VERSION 5.7 ;
BUSBITCHARS "[]" ;
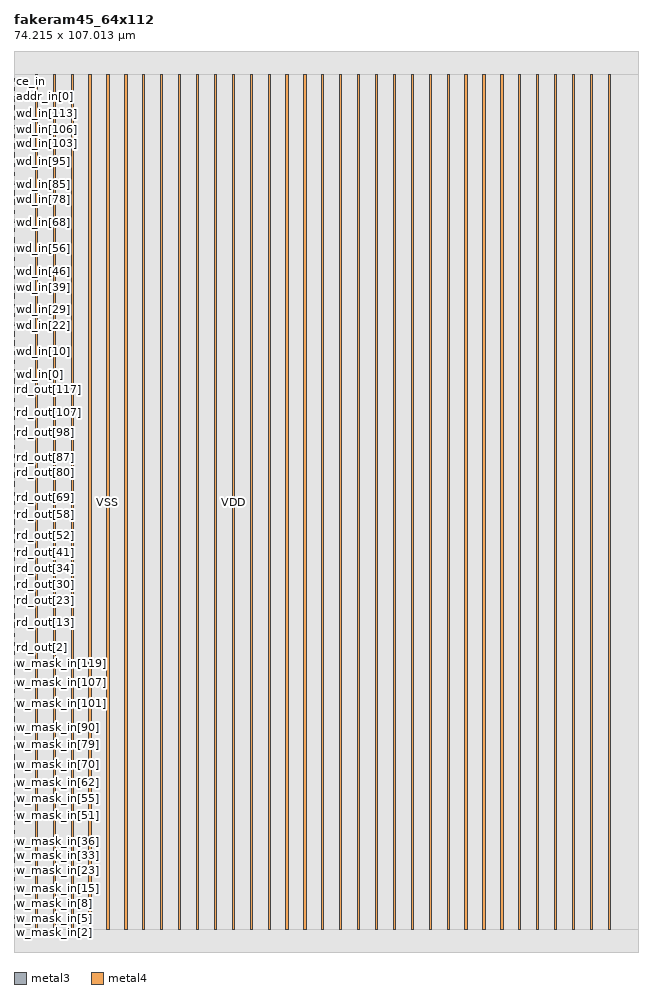
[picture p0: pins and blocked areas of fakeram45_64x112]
MACRO fakeram45_64x112
  FOREIGN fakeram45_64x112 0 0 ;
  SYMMETRY X Y R90 ;
  SIZE 74.215 BY 107.013 ;
  CLASS BLOCK ;
  PIN w_mask_in[0]
    DIRECTION INPUT ;
    USE SIGNAL ;
    SHAPE ABUTMENT ;
    PORT
      LAYER metal3 ;
      RECT 0.000 2.661 0.067 2.728 ;
    END
  END w_mask_in[0]
  PIN w_mask_in[1]
    DIRECTION INPUT ;
    USE SIGNAL ;
    SHAPE ABUTMENT ;
    PORT
      LAYER metal3 ;
      RECT 0.000 2.927 0.067 2.994 ;
    END
  END w_mask_in[1]
  PIN w_mask_in[2]
    DIRECTION INPUT ;
    USE SIGNAL ;
    SHAPE ABUTMENT ;
    PORT
      LAYER metal3 ;
      RECT 0.000 3.193 0.067 3.260 ;
    END
  END w_mask_in[2]
  PIN w_mask_in[3]
    DIRECTION INPUT ;
    USE SIGNAL ;
    SHAPE ABUTMENT ;
    PORT
      LAYER metal3 ;
      RECT 0.000 3.459 0.067 3.526 ;
    END
  END w_mask_in[3]
  PIN w_mask_in[4]
    DIRECTION INPUT ;
    USE SIGNAL ;
    SHAPE ABUTMENT ;
    PORT
      LAYER metal3 ;
      RECT 0.000 3.725 0.067 3.792 ;
    END
  END w_mask_in[4]
  PIN w_mask_in[5]
    DIRECTION INPUT ;
    USE SIGNAL ;
    SHAPE ABUTMENT ;
    PORT
      LAYER metal3 ;
      RECT 0.000 3.992 0.067 4.058 ;
    END
  END w_mask_in[5]
  PIN w_mask_in[6]
    DIRECTION INPUT ;
    USE SIGNAL ;
    SHAPE ABUTMENT ;
    PORT
      LAYER metal3 ;
      RECT 0.000 4.258 0.067 4.324 ;
    END
  END w_mask_in[6]
  PIN w_mask_in[7]
    DIRECTION INPUT ;
    USE SIGNAL ;
    SHAPE ABUTMENT ;
    PORT
      LAYER metal3 ;
      RECT 0.000 4.524 0.067 4.590 ;
    END
  END w_mask_in[7]
  PIN w_mask_in[8]
    DIRECTION INPUT ;
    USE SIGNAL ;
    SHAPE ABUTMENT ;
    PORT
      LAYER metal3 ;
      RECT 0.000 4.790 0.067 4.856 ;
    END
  END w_mask_in[8]
  PIN w_mask_in[9]
    DIRECTION INPUT ;
    USE SIGNAL ;
    SHAPE ABUTMENT ;
    PORT
      LAYER metal3 ;
      RECT 0.000 5.056 0.067 5.123 ;
    END
  END w_mask_in[9]
  PIN w_mask_in[10]
    DIRECTION INPUT ;
    USE SIGNAL ;
    SHAPE ABUTMENT ;
    PORT
      LAYER metal3 ;
      RECT 0.000 5.322 0.067 5.389 ;
    END
  END w_mask_in[10]
  PIN w_mask_in[11]
    DIRECTION INPUT ;
    USE SIGNAL ;
    SHAPE ABUTMENT ;
    PORT
      LAYER metal3 ;
      RECT 0.000 5.588 0.067 5.655 ;
    END
  END w_mask_in[11]
  PIN w_mask_in[12]
    DIRECTION INPUT ;
    USE SIGNAL ;
    SHAPE ABUTMENT ;
    PORT
      LAYER metal3 ;
      RECT 0.000 5.854 0.067 5.921 ;
    END
  END w_mask_in[12]
  PIN w_mask_in[13]
    DIRECTION INPUT ;
    USE SIGNAL ;
    SHAPE ABUTMENT ;
    PORT
      LAYER metal3 ;
      RECT 0.000 6.120 0.067 6.187 ;
    END
  END w_mask_in[13]
  PIN w_mask_in[14]
    DIRECTION INPUT ;
    USE SIGNAL ;
    SHAPE ABUTMENT ;
    PORT
      LAYER metal3 ;
      RECT 0.000 6.387 0.067 6.453 ;
    END
  END w_mask_in[14]
  PIN w_mask_in[15]
    DIRECTION INPUT ;
    USE SIGNAL ;
    SHAPE ABUTMENT ;
    PORT
      LAYER metal3 ;
      RECT 0.000 6.653 0.067 6.719 ;
    END
  END w_mask_in[15]
  PIN w_mask_in[16]
    DIRECTION INPUT ;
    USE SIGNAL ;
    SHAPE ABUTMENT ;
    PORT
      LAYER metal3 ;
      RECT 0.000 6.919 0.067 6.985 ;
    END
  END w_mask_in[16]
  PIN w_mask_in[17]
    DIRECTION INPUT ;
    USE SIGNAL ;
    SHAPE ABUTMENT ;
    PORT
      LAYER metal3 ;
      RECT 0.000 7.185 0.067 7.251 ;
    END
  END w_mask_in[17]
  PIN w_mask_in[18]
    DIRECTION INPUT ;
    USE SIGNAL ;
    SHAPE ABUTMENT ;
    PORT
      LAYER metal3 ;
      RECT 0.000 7.451 0.067 7.518 ;
    END
  END w_mask_in[18]
  PIN w_mask_in[19]
    DIRECTION INPUT ;
    USE SIGNAL ;
    SHAPE ABUTMENT ;
    PORT
      LAYER metal3 ;
      RECT 0.000 7.717 0.067 7.784 ;
    END
  END w_mask_in[19]
  PIN w_mask_in[20]
    DIRECTION INPUT ;
    USE SIGNAL ;
    SHAPE ABUTMENT ;
    PORT
      LAYER metal3 ;
      RECT 0.000 7.983 0.067 8.050 ;
    END
  END w_mask_in[20]
  PIN w_mask_in[21]
    DIRECTION INPUT ;
    USE SIGNAL ;
    SHAPE ABUTMENT ;
    PORT
      LAYER metal3 ;
      RECT 0.000 8.249 0.067 8.316 ;
    END
  END w_mask_in[21]
  PIN w_mask_in[22]
    DIRECTION INPUT ;
    USE SIGNAL ;
    SHAPE ABUTMENT ;
    PORT
      LAYER metal3 ;
      RECT 0.000 8.515 0.067 8.582 ;
    END
  END w_mask_in[22]
  PIN w_mask_in[23]
    DIRECTION INPUT ;
    USE SIGNAL ;
    SHAPE ABUTMENT ;
    PORT
      LAYER metal3 ;
      RECT 0.000 8.782 0.067 8.848 ;
    END
  END w_mask_in[23]
  PIN w_mask_in[24]
    DIRECTION INPUT ;
    USE SIGNAL ;
    SHAPE ABUTMENT ;
    PORT
      LAYER metal3 ;
      RECT 0.000 9.048 0.067 9.114 ;
    END
  END w_mask_in[24]
  PIN w_mask_in[25]
    DIRECTION INPUT ;
    USE SIGNAL ;
    SHAPE ABUTMENT ;
    PORT
      LAYER metal3 ;
      RECT 0.000 9.314 0.067 9.380 ;
    END
  END w_mask_in[25]
  PIN w_mask_in[26]
    DIRECTION INPUT ;
    USE SIGNAL ;
    SHAPE ABUTMENT ;
    PORT
      LAYER metal3 ;
      RECT 0.000 9.580 0.067 9.646 ;
    END
  END w_mask_in[26]
  PIN w_mask_in[27]
    DIRECTION INPUT ;
    USE SIGNAL ;
    SHAPE ABUTMENT ;
    PORT
      LAYER metal3 ;
      RECT 0.000 9.846 0.067 9.912 ;
    END
  END w_mask_in[27]
  PIN w_mask_in[28]
    DIRECTION INPUT ;
    USE SIGNAL ;
    SHAPE ABUTMENT ;
    PORT
      LAYER metal3 ;
      RECT 0.000 10.112 0.067 10.179 ;
    END
  END w_mask_in[28]
  PIN w_mask_in[29]
    DIRECTION INPUT ;
    USE SIGNAL ;
    SHAPE ABUTMENT ;
    PORT
      LAYER metal3 ;
      RECT 0.000 10.378 0.067 10.445 ;
    END
  END w_mask_in[29]
  PIN w_mask_in[30]
    DIRECTION INPUT ;
    USE SIGNAL ;
    SHAPE ABUTMENT ;
    PORT
      LAYER metal3 ;
      RECT 0.000 10.644 0.067 10.711 ;
    END
  END w_mask_in[30]
  PIN w_mask_in[31]
    DIRECTION INPUT ;
    USE SIGNAL ;
    SHAPE ABUTMENT ;
    PORT
      LAYER metal3 ;
      RECT 0.000 10.910 0.067 10.977 ;
    END
  END w_mask_in[31]
  PIN w_mask_in[32]
    DIRECTION INPUT ;
    USE SIGNAL ;
    SHAPE ABUTMENT ;
    PORT
      LAYER metal3 ;
      RECT 0.000 11.176 0.067 11.243 ;
    END
  END w_mask_in[32]
  PIN w_mask_in[33]
    DIRECTION INPUT ;
    USE SIGNAL ;
    SHAPE ABUTMENT ;
    PORT
      LAYER metal3 ;
      RECT 0.000 11.443 0.067 11.509 ;
    END
  END w_mask_in[33]
  PIN w_mask_in[34]
    DIRECTION INPUT ;
    USE SIGNAL ;
    SHAPE ABUTMENT ;
    PORT
      LAYER metal3 ;
      RECT 0.000 11.709 0.067 11.775 ;
    END
  END w_mask_in[34]
  PIN w_mask_in[35]
    DIRECTION INPUT ;
    USE SIGNAL ;
    SHAPE ABUTMENT ;
    PORT
      LAYER metal3 ;
      RECT 0.000 11.975 0.067 12.041 ;
    END
  END w_mask_in[35]
  PIN w_mask_in[36]
    DIRECTION INPUT ;
    USE SIGNAL ;
    SHAPE ABUTMENT ;
    PORT
      LAYER metal3 ;
      RECT 0.000 12.241 0.067 12.307 ;
    END
  END w_mask_in[36]
  PIN w_mask_in[37]
    DIRECTION INPUT ;
    USE SIGNAL ;
    SHAPE ABUTMENT ;
    PORT
      LAYER metal3 ;
      RECT 0.000 12.507 0.067 12.574 ;
    END
  END w_mask_in[37]
  PIN w_mask_in[38]
    DIRECTION INPUT ;
    USE SIGNAL ;
    SHAPE ABUTMENT ;
    PORT
      LAYER metal3 ;
      RECT 0.000 12.773 0.067 12.840 ;
    END
  END w_mask_in[38]
  PIN w_mask_in[39]
    DIRECTION INPUT ;
    USE SIGNAL ;
    SHAPE ABUTMENT ;
    PORT
      LAYER metal3 ;
      RECT 0.000 13.039 0.067 13.106 ;
    END
  END w_mask_in[39]
  PIN w_mask_in[40]
    DIRECTION INPUT ;
    USE SIGNAL ;
    SHAPE ABUTMENT ;
    PORT
      LAYER metal3 ;
      RECT 0.000 13.305 0.067 13.372 ;
    END
  END w_mask_in[40]
  PIN w_mask_in[41]
    DIRECTION INPUT ;
    USE SIGNAL ;
    SHAPE ABUTMENT ;
    PORT
      LAYER metal3 ;
      RECT 0.000 13.571 0.067 13.638 ;
    END
  END w_mask_in[41]
  PIN w_mask_in[42]
    DIRECTION INPUT ;
    USE SIGNAL ;
    SHAPE ABUTMENT ;
    PORT
      LAYER metal3 ;
      RECT 0.000 13.838 0.067 13.904 ;
    END
  END w_mask_in[42]
  PIN w_mask_in[43]
    DIRECTION INPUT ;
    USE SIGNAL ;
    SHAPE ABUTMENT ;
    PORT
      LAYER metal3 ;
      RECT 0.000 14.104 0.067 14.170 ;
    END
  END w_mask_in[43]
  PIN w_mask_in[44]
    DIRECTION INPUT ;
    USE SIGNAL ;
    SHAPE ABUTMENT ;
    PORT
      LAYER metal3 ;
      RECT 0.000 14.370 0.067 14.436 ;
    END
  END w_mask_in[44]
  PIN w_mask_in[45]
    DIRECTION INPUT ;
    USE SIGNAL ;
    SHAPE ABUTMENT ;
    PORT
      LAYER metal3 ;
      RECT 0.000 14.636 0.067 14.702 ;
    END
  END w_mask_in[45]
  PIN w_mask_in[46]
    DIRECTION INPUT ;
    USE SIGNAL ;
    SHAPE ABUTMENT ;
    PORT
      LAYER metal3 ;
      RECT 0.000 14.902 0.067 14.969 ;
    END
  END w_mask_in[46]
  PIN w_mask_in[47]
    DIRECTION INPUT ;
    USE SIGNAL ;
    SHAPE ABUTMENT ;
    PORT
      LAYER metal3 ;
      RECT 0.000 15.168 0.067 15.235 ;
    END
  END w_mask_in[47]
  PIN w_mask_in[48]
    DIRECTION INPUT ;
    USE SIGNAL ;
    SHAPE ABUTMENT ;
    PORT
      LAYER metal3 ;
      RECT 0.000 15.434 0.067 15.501 ;
    END
  END w_mask_in[48]
  PIN w_mask_in[49]
    DIRECTION INPUT ;
    USE SIGNAL ;
    SHAPE ABUTMENT ;
    PORT
      LAYER metal3 ;
      RECT 0.000 15.700 0.067 15.767 ;
    END
  END w_mask_in[49]
  PIN w_mask_in[50]
    DIRECTION INPUT ;
    USE SIGNAL ;
    SHAPE ABUTMENT ;
    PORT
      LAYER metal3 ;
      RECT 0.000 15.966 0.067 16.033 ;
    END
  END w_mask_in[50]
  PIN w_mask_in[51]
    DIRECTION INPUT ;
    USE SIGNAL ;
    SHAPE ABUTMENT ;
    PORT
      LAYER metal3 ;
      RECT 0.000 16.233 0.067 16.299 ;
    END
  END w_mask_in[51]
  PIN w_mask_in[52]
    DIRECTION INPUT ;
    USE SIGNAL ;
    SHAPE ABUTMENT ;
    PORT
      LAYER metal3 ;
      RECT 0.000 16.499 0.067 16.565 ;
    END
  END w_mask_in[52]
  PIN w_mask_in[53]
    DIRECTION INPUT ;
    USE SIGNAL ;
    SHAPE ABUTMENT ;
    PORT
      LAYER metal3 ;
      RECT 0.000 16.765 0.067 16.831 ;
    END
  END w_mask_in[53]
  PIN w_mask_in[54]
    DIRECTION INPUT ;
    USE SIGNAL ;
    SHAPE ABUTMENT ;
    PORT
      LAYER metal3 ;
      RECT 0.000 17.031 0.067 17.097 ;
    END
  END w_mask_in[54]
  PIN w_mask_in[55]
    DIRECTION INPUT ;
    USE SIGNAL ;
    SHAPE ABUTMENT ;
    PORT
      LAYER metal3 ;
      RECT 0.000 17.297 0.067 17.363 ;
    END
  END w_mask_in[55]
  PIN w_mask_in[56]
    DIRECTION INPUT ;
    USE SIGNAL ;
    SHAPE ABUTMENT ;
    PORT
      LAYER metal3 ;
      RECT 0.000 17.563 0.067 17.630 ;
    END
  END w_mask_in[56]
  PIN w_mask_in[57]
    DIRECTION INPUT ;
    USE SIGNAL ;
    SHAPE ABUTMENT ;
    PORT
      LAYER metal3 ;
      RECT 0.000 17.829 0.067 17.896 ;
    END
  END w_mask_in[57]
  PIN w_mask_in[58]
    DIRECTION INPUT ;
    USE SIGNAL ;
    SHAPE ABUTMENT ;
    PORT
      LAYER metal3 ;
      RECT 0.000 18.095 0.067 18.162 ;
    END
  END w_mask_in[58]
  PIN w_mask_in[59]
    DIRECTION INPUT ;
    USE SIGNAL ;
    SHAPE ABUTMENT ;
    PORT
      LAYER metal3 ;
      RECT 0.000 18.361 0.067 18.428 ;
    END
  END w_mask_in[59]
  PIN w_mask_in[60]
    DIRECTION INPUT ;
    USE SIGNAL ;
    SHAPE ABUTMENT ;
    PORT
      LAYER metal3 ;
      RECT 0.000 18.627 0.067 18.694 ;
    END
  END w_mask_in[60]
  PIN w_mask_in[61]
    DIRECTION INPUT ;
    USE SIGNAL ;
    SHAPE ABUTMENT ;
    PORT
      LAYER metal3 ;
      RECT 0.000 18.894 0.067 18.960 ;
    END
  END w_mask_in[61]
  PIN w_mask_in[62]
    DIRECTION INPUT ;
    USE SIGNAL ;
    SHAPE ABUTMENT ;
    PORT
      LAYER metal3 ;
      RECT 0.000 19.160 0.067 19.226 ;
    END
  END w_mask_in[62]
  PIN w_mask_in[63]
    DIRECTION INPUT ;
    USE SIGNAL ;
    SHAPE ABUTMENT ;
    PORT
      LAYER metal3 ;
      RECT 0.000 19.426 0.067 19.492 ;
    END
  END w_mask_in[63]
  PIN w_mask_in[64]
    DIRECTION INPUT ;
    USE SIGNAL ;
    SHAPE ABUTMENT ;
    PORT
      LAYER metal3 ;
      RECT 0.000 19.692 0.067 19.758 ;
    END
  END w_mask_in[64]
  PIN w_mask_in[65]
    DIRECTION INPUT ;
    USE SIGNAL ;
    SHAPE ABUTMENT ;
    PORT
      LAYER metal3 ;
      RECT 0.000 19.958 0.067 20.025 ;
    END
  END w_mask_in[65]
  PIN w_mask_in[66]
    DIRECTION INPUT ;
    USE SIGNAL ;
    SHAPE ABUTMENT ;
    PORT
      LAYER metal3 ;
      RECT 0.000 20.224 0.067 20.291 ;
    END
  END w_mask_in[66]
  PIN w_mask_in[67]
    DIRECTION INPUT ;
    USE SIGNAL ;
    SHAPE ABUTMENT ;
    PORT
      LAYER metal3 ;
      RECT 0.000 20.490 0.067 20.557 ;
    END
  END w_mask_in[67]
  PIN w_mask_in[68]
    DIRECTION INPUT ;
    USE SIGNAL ;
    SHAPE ABUTMENT ;
    PORT
      LAYER metal3 ;
      RECT 0.000 20.756 0.067 20.823 ;
    END
  END w_mask_in[68]
  PIN w_mask_in[69]
    DIRECTION INPUT ;
    USE SIGNAL ;
    SHAPE ABUTMENT ;
    PORT
      LAYER metal3 ;
      RECT 0.000 21.022 0.067 21.089 ;
    END
  END w_mask_in[69]
  PIN w_mask_in[70]
    DIRECTION INPUT ;
    USE SIGNAL ;
    SHAPE ABUTMENT ;
    PORT
      LAYER metal3 ;
      RECT 0.000 21.289 0.067 21.355 ;
    END
  END w_mask_in[70]
  PIN w_mask_in[71]
    DIRECTION INPUT ;
    USE SIGNAL ;
    SHAPE ABUTMENT ;
    PORT
      LAYER metal3 ;
      RECT 0.000 21.555 0.067 21.621 ;
    END
  END w_mask_in[71]
  PIN w_mask_in[72]
    DIRECTION INPUT ;
    USE SIGNAL ;
    SHAPE ABUTMENT ;
    PORT
      LAYER metal3 ;
      RECT 0.000 21.821 0.067 21.887 ;
    END
  END w_mask_in[72]
  PIN w_mask_in[73]
    DIRECTION INPUT ;
    USE SIGNAL ;
    SHAPE ABUTMENT ;
    PORT
      LAYER metal3 ;
      RECT 0.000 22.087 0.067 22.153 ;
    END
  END w_mask_in[73]
  PIN w_mask_in[74]
    DIRECTION INPUT ;
    USE SIGNAL ;
    SHAPE ABUTMENT ;
    PORT
      LAYER metal3 ;
      RECT 0.000 22.353 0.067 22.420 ;
    END
  END w_mask_in[74]
  PIN w_mask_in[75]
    DIRECTION INPUT ;
    USE SIGNAL ;
    SHAPE ABUTMENT ;
    PORT
      LAYER metal3 ;
      RECT 0.000 22.619 0.067 22.686 ;
    END
  END w_mask_in[75]
  PIN w_mask_in[76]
    DIRECTION INPUT ;
    USE SIGNAL ;
    SHAPE ABUTMENT ;
    PORT
      LAYER metal3 ;
      RECT 0.000 22.885 0.067 22.952 ;
    END
  END w_mask_in[76]
  PIN w_mask_in[77]
    DIRECTION INPUT ;
    USE SIGNAL ;
    SHAPE ABUTMENT ;
    PORT
      LAYER metal3 ;
      RECT 0.000 23.151 0.067 23.218 ;
    END
  END w_mask_in[77]
  PIN w_mask_in[78]
    DIRECTION INPUT ;
    USE SIGNAL ;
    SHAPE ABUTMENT ;
    PORT
      LAYER metal3 ;
      RECT 0.000 23.417 0.067 23.484 ;
    END
  END w_mask_in[78]
  PIN w_mask_in[79]
    DIRECTION INPUT ;
    USE SIGNAL ;
    SHAPE ABUTMENT ;
    PORT
      LAYER metal3 ;
      RECT 0.000 23.684 0.067 23.750 ;
    END
  END w_mask_in[79]
  PIN w_mask_in[80]
    DIRECTION INPUT ;
    USE SIGNAL ;
    SHAPE ABUTMENT ;
    PORT
      LAYER metal3 ;
      RECT 0.000 23.950 0.067 24.016 ;
    END
  END w_mask_in[80]
  PIN w_mask_in[81]
    DIRECTION INPUT ;
    USE SIGNAL ;
    SHAPE ABUTMENT ;
    PORT
      LAYER metal3 ;
      RECT 0.000 24.216 0.067 24.282 ;
    END
  END w_mask_in[81]
  PIN w_mask_in[82]
    DIRECTION INPUT ;
    USE SIGNAL ;
    SHAPE ABUTMENT ;
    PORT
      LAYER metal3 ;
      RECT 0.000 24.482 0.067 24.548 ;
    END
  END w_mask_in[82]
  PIN w_mask_in[83]
    DIRECTION INPUT ;
    USE SIGNAL ;
    SHAPE ABUTMENT ;
    PORT
      LAYER metal3 ;
      RECT 0.000 24.748 0.067 24.814 ;
    END
  END w_mask_in[83]
  PIN w_mask_in[84]
    DIRECTION INPUT ;
    USE SIGNAL ;
    SHAPE ABUTMENT ;
    PORT
      LAYER metal3 ;
      RECT 0.000 25.014 0.067 25.081 ;
    END
  END w_mask_in[84]
  PIN w_mask_in[85]
    DIRECTION INPUT ;
    USE SIGNAL ;
    SHAPE ABUTMENT ;
    PORT
      LAYER metal3 ;
      RECT 0.000 25.280 0.067 25.347 ;
    END
  END w_mask_in[85]
  PIN w_mask_in[86]
    DIRECTION INPUT ;
    USE SIGNAL ;
    SHAPE ABUTMENT ;
    PORT
      LAYER metal3 ;
      RECT 0.000 25.546 0.067 25.613 ;
    END
  END w_mask_in[86]
  PIN w_mask_in[87]
    DIRECTION INPUT ;
    USE SIGNAL ;
    SHAPE ABUTMENT ;
    PORT
      LAYER metal3 ;
      RECT 0.000 25.812 0.067 25.879 ;
    END
  END w_mask_in[87]
  PIN w_mask_in[88]
    DIRECTION INPUT ;
    USE SIGNAL ;
    SHAPE ABUTMENT ;
    PORT
      LAYER metal3 ;
      RECT 0.000 26.078 0.067 26.145 ;
    END
  END w_mask_in[88]
  PIN w_mask_in[89]
    DIRECTION INPUT ;
    USE SIGNAL ;
    SHAPE ABUTMENT ;
    PORT
      LAYER metal3 ;
      RECT 0.000 26.345 0.067 26.411 ;
    END
  END w_mask_in[89]
  PIN w_mask_in[90]
    DIRECTION INPUT ;
    USE SIGNAL ;
    SHAPE ABUTMENT ;
    PORT
      LAYER metal3 ;
      RECT 0.000 26.611 0.067 26.677 ;
    END
  END w_mask_in[90]
  PIN w_mask_in[91]
    DIRECTION INPUT ;
    USE SIGNAL ;
    SHAPE ABUTMENT ;
    PORT
      LAYER metal3 ;
      RECT 0.000 26.877 0.067 26.943 ;
    END
  END w_mask_in[91]
  PIN w_mask_in[92]
    DIRECTION INPUT ;
    USE SIGNAL ;
    SHAPE ABUTMENT ;
    PORT
      LAYER metal3 ;
      RECT 0.000 27.143 0.067 27.209 ;
    END
  END w_mask_in[92]
  PIN w_mask_in[93]
    DIRECTION INPUT ;
    USE SIGNAL ;
    SHAPE ABUTMENT ;
    PORT
      LAYER metal3 ;
      RECT 0.000 27.409 0.067 27.476 ;
    END
  END w_mask_in[93]
  PIN w_mask_in[94]
    DIRECTION INPUT ;
    USE SIGNAL ;
    SHAPE ABUTMENT ;
    PORT
      LAYER metal3 ;
      RECT 0.000 27.675 0.067 27.742 ;
    END
  END w_mask_in[94]
  PIN w_mask_in[95]
    DIRECTION INPUT ;
    USE SIGNAL ;
    SHAPE ABUTMENT ;
    PORT
      LAYER metal3 ;
      RECT 0.000 27.941 0.067 28.008 ;
    END
  END w_mask_in[95]
  PIN w_mask_in[96]
    DIRECTION INPUT ;
    USE SIGNAL ;
    SHAPE ABUTMENT ;
    PORT
      LAYER metal3 ;
      RECT 0.000 28.207 0.067 28.274 ;
    END
  END w_mask_in[96]
  PIN w_mask_in[97]
    DIRECTION INPUT ;
    USE SIGNAL ;
    SHAPE ABUTMENT ;
    PORT
      LAYER metal3 ;
      RECT 0.000 28.473 0.067 28.540 ;
    END
  END w_mask_in[97]
  PIN w_mask_in[98]
    DIRECTION INPUT ;
    USE SIGNAL ;
    SHAPE ABUTMENT ;
    PORT
      LAYER metal3 ;
      RECT 0.000 28.740 0.067 28.806 ;
    END
  END w_mask_in[98]
  PIN w_mask_in[99]
    DIRECTION INPUT ;
    USE SIGNAL ;
    SHAPE ABUTMENT ;
    PORT
      LAYER metal3 ;
      RECT 0.000 29.006 0.067 29.072 ;
    END
  END w_mask_in[99]
  PIN w_mask_in[100]
    DIRECTION INPUT ;
    USE SIGNAL ;
    SHAPE ABUTMENT ;
    PORT
      LAYER metal3 ;
      RECT 0.000 29.272 0.067 29.338 ;
    END
  END w_mask_in[100]
  PIN w_mask_in[101]
    DIRECTION INPUT ;
    USE SIGNAL ;
    SHAPE ABUTMENT ;
    PORT
      LAYER metal3 ;
      RECT 0.000 29.538 0.067 29.604 ;
    END
  END w_mask_in[101]
  PIN w_mask_in[102]
    DIRECTION INPUT ;
    USE SIGNAL ;
    SHAPE ABUTMENT ;
    PORT
      LAYER metal3 ;
      RECT 0.000 29.804 0.067 29.871 ;
    END
  END w_mask_in[102]
  PIN w_mask_in[103]
    DIRECTION INPUT ;
    USE SIGNAL ;
    SHAPE ABUTMENT ;
    PORT
      LAYER metal3 ;
      RECT 0.000 30.070 0.067 30.137 ;
    END
  END w_mask_in[103]
  PIN w_mask_in[104]
    DIRECTION INPUT ;
    USE SIGNAL ;
    SHAPE ABUTMENT ;
    PORT
      LAYER metal3 ;
      RECT 0.000 30.336 0.067 30.403 ;
    END
  END w_mask_in[104]
  PIN w_mask_in[105]
    DIRECTION INPUT ;
    USE SIGNAL ;
    SHAPE ABUTMENT ;
    PORT
      LAYER metal3 ;
      RECT 0.000 30.602 0.067 30.669 ;
    END
  END w_mask_in[105]
  PIN w_mask_in[106]
    DIRECTION INPUT ;
    USE SIGNAL ;
    SHAPE ABUTMENT ;
    PORT
      LAYER metal3 ;
      RECT 0.000 30.868 0.067 30.935 ;
    END
  END w_mask_in[106]
  PIN w_mask_in[107]
    DIRECTION INPUT ;
    USE SIGNAL ;
    SHAPE ABUTMENT ;
    PORT
      LAYER metal3 ;
      RECT 0.000 31.135 0.067 31.201 ;
    END
  END w_mask_in[107]
  PIN w_mask_in[108]
    DIRECTION INPUT ;
    USE SIGNAL ;
    SHAPE ABUTMENT ;
    PORT
      LAYER metal3 ;
      RECT 0.000 31.401 0.067 31.467 ;
    END
  END w_mask_in[108]
  PIN w_mask_in[109]
    DIRECTION INPUT ;
    USE SIGNAL ;
    SHAPE ABUTMENT ;
    PORT
      LAYER metal3 ;
      RECT 0.000 31.667 0.067 31.733 ;
    END
  END w_mask_in[109]
  PIN w_mask_in[110]
    DIRECTION INPUT ;
    USE SIGNAL ;
    SHAPE ABUTMENT ;
    PORT
      LAYER metal3 ;
      RECT 0.000 31.933 0.067 31.999 ;
    END
  END w_mask_in[110]
  PIN w_mask_in[111]
    DIRECTION INPUT ;
    USE SIGNAL ;
    SHAPE ABUTMENT ;
    PORT
      LAYER metal3 ;
      RECT 0.000 32.199 0.067 32.265 ;
    END
  END w_mask_in[111]
  PIN w_mask_in[112]
    DIRECTION INPUT ;
    USE SIGNAL ;
    SHAPE ABUTMENT ;
    PORT
      LAYER metal3 ;
      RECT 0.000 32.465 0.067 32.532 ;
    END
  END w_mask_in[112]
  PIN w_mask_in[113]
    DIRECTION INPUT ;
    USE SIGNAL ;
    SHAPE ABUTMENT ;
    PORT
      LAYER metal3 ;
      RECT 0.000 32.731 0.067 32.798 ;
    END
  END w_mask_in[113]
  PIN w_mask_in[114]
    DIRECTION INPUT ;
    USE SIGNAL ;
    SHAPE ABUTMENT ;
    PORT
      LAYER metal3 ;
      RECT 0.000 32.997 0.067 33.064 ;
    END
  END w_mask_in[114]
  PIN w_mask_in[115]
    DIRECTION INPUT ;
    USE SIGNAL ;
    SHAPE ABUTMENT ;
    PORT
      LAYER metal3 ;
      RECT 0.000 33.263 0.067 33.330 ;
    END
  END w_mask_in[115]
  PIN w_mask_in[116]
    DIRECTION INPUT ;
    USE SIGNAL ;
    SHAPE ABUTMENT ;
    PORT
      LAYER metal3 ;
      RECT 0.000 33.529 0.067 33.596 ;
    END
  END w_mask_in[116]
  PIN w_mask_in[117]
    DIRECTION INPUT ;
    USE SIGNAL ;
    SHAPE ABUTMENT ;
    PORT
      LAYER metal3 ;
      RECT 0.000 33.796 0.067 33.862 ;
    END
  END w_mask_in[117]
  PIN w_mask_in[118]
    DIRECTION INPUT ;
    USE SIGNAL ;
    SHAPE ABUTMENT ;
    PORT
      LAYER metal3 ;
      RECT 0.000 34.062 0.067 34.128 ;
    END
  END w_mask_in[118]
  PIN w_mask_in[119]
    DIRECTION INPUT ;
    USE SIGNAL ;
    SHAPE ABUTMENT ;
    PORT
      LAYER metal3 ;
      RECT 0.000 34.328 0.067 34.394 ;
    END
  END w_mask_in[119]
  PIN w_mask_in[120]
    DIRECTION INPUT ;
    USE SIGNAL ;
    SHAPE ABUTMENT ;
    PORT
      LAYER metal3 ;
      RECT 0.000 34.594 0.067 34.660 ;
    END
  END w_mask_in[120]
  PIN w_mask_in[121]
    DIRECTION INPUT ;
    USE SIGNAL ;
    SHAPE ABUTMENT ;
    PORT
      LAYER metal3 ;
      RECT 0.000 34.860 0.067 34.927 ;
    END
  END w_mask_in[121]
  PIN w_mask_in[122]
    DIRECTION INPUT ;
    USE SIGNAL ;
    SHAPE ABUTMENT ;
    PORT
      LAYER metal3 ;
      RECT 0.000 35.126 0.067 35.193 ;
    END
  END w_mask_in[122]
  PIN w_mask_in[123]
    DIRECTION INPUT ;
    USE SIGNAL ;
    SHAPE ABUTMENT ;
    PORT
      LAYER metal3 ;
      RECT 0.000 35.392 0.067 35.459 ;
    END
  END w_mask_in[123]
  PIN rd_out[0]
    DIRECTION OUTPUT ;
    USE SIGNAL ;
    SHAPE ABUTMENT ;
    PORT
      LAYER metal3 ;
      RECT 0.000 35.658 0.067 35.725 ;
    END
  END rd_out[0]
  PIN rd_out[1]
    DIRECTION OUTPUT ;
    USE SIGNAL ;
    SHAPE ABUTMENT ;
    PORT
      LAYER metal3 ;
      RECT 0.000 35.924 0.067 35.991 ;
    END
  END rd_out[1]
  PIN rd_out[2]
    DIRECTION OUTPUT ;
    USE SIGNAL ;
    SHAPE ABUTMENT ;
    PORT
      LAYER metal3 ;
      RECT 0.000 36.191 0.067 36.257 ;
    END
  END rd_out[2]
  PIN rd_out[3]
    DIRECTION OUTPUT ;
    USE SIGNAL ;
    SHAPE ABUTMENT ;
    PORT
      LAYER metal3 ;
      RECT 0.000 36.457 0.067 36.523 ;
    END
  END rd_out[3]
  PIN rd_out[4]
    DIRECTION OUTPUT ;
    USE SIGNAL ;
    SHAPE ABUTMENT ;
    PORT
      LAYER metal3 ;
      RECT 0.000 36.723 0.067 36.789 ;
    END
  END rd_out[4]
  PIN rd_out[5]
    DIRECTION OUTPUT ;
    USE SIGNAL ;
    SHAPE ABUTMENT ;
    PORT
      LAYER metal3 ;
      RECT 0.000 36.989 0.067 37.055 ;
    END
  END rd_out[5]
  PIN rd_out[6]
    DIRECTION OUTPUT ;
    USE SIGNAL ;
    SHAPE ABUTMENT ;
    PORT
      LAYER metal3 ;
      RECT 0.000 37.255 0.067 37.321 ;
    END
  END rd_out[6]
  PIN rd_out[7]
    DIRECTION OUTPUT ;
    USE SIGNAL ;
    SHAPE ABUTMENT ;
    PORT
      LAYER metal3 ;
      RECT 0.000 37.521 0.067 37.588 ;
    END
  END rd_out[7]
  PIN rd_out[8]
    DIRECTION OUTPUT ;
    USE SIGNAL ;
    SHAPE ABUTMENT ;
    PORT
      LAYER metal3 ;
      RECT 0.000 37.787 0.067 37.854 ;
    END
  END rd_out[8]
  PIN rd_out[9]
    DIRECTION OUTPUT ;
    USE SIGNAL ;
    SHAPE ABUTMENT ;
    PORT
      LAYER metal3 ;
      RECT 0.000 38.053 0.067 38.120 ;
    END
  END rd_out[9]
  PIN rd_out[10]
    DIRECTION OUTPUT ;
    USE SIGNAL ;
    SHAPE ABUTMENT ;
    PORT
      LAYER metal3 ;
      RECT 0.000 38.319 0.067 38.386 ;
    END
  END rd_out[10]
  PIN rd_out[11]
    DIRECTION OUTPUT ;
    USE SIGNAL ;
    SHAPE ABUTMENT ;
    PORT
      LAYER metal3 ;
      RECT 0.000 38.586 0.067 38.652 ;
    END
  END rd_out[11]
  PIN rd_out[12]
    DIRECTION OUTPUT ;
    USE SIGNAL ;
    SHAPE ABUTMENT ;
    PORT
      LAYER metal3 ;
      RECT 0.000 38.852 0.067 38.918 ;
    END
  END rd_out[12]
  PIN rd_out[13]
    DIRECTION OUTPUT ;
    USE SIGNAL ;
    SHAPE ABUTMENT ;
    PORT
      LAYER metal3 ;
      RECT 0.000 39.118 0.067 39.184 ;
    END
  END rd_out[13]
  PIN rd_out[14]
    DIRECTION OUTPUT ;
    USE SIGNAL ;
    SHAPE ABUTMENT ;
    PORT
      LAYER metal3 ;
      RECT 0.000 39.384 0.067 39.450 ;
    END
  END rd_out[14]
  PIN rd_out[15]
    DIRECTION OUTPUT ;
    USE SIGNAL ;
    SHAPE ABUTMENT ;
    PORT
      LAYER metal3 ;
      RECT 0.000 39.650 0.067 39.716 ;
    END
  END rd_out[15]
  PIN rd_out[16]
    DIRECTION OUTPUT ;
    USE SIGNAL ;
    SHAPE ABUTMENT ;
    PORT
      LAYER metal3 ;
      RECT 0.000 39.916 0.067 39.983 ;
    END
  END rd_out[16]
  PIN rd_out[17]
    DIRECTION OUTPUT ;
    USE SIGNAL ;
    SHAPE ABUTMENT ;
    PORT
      LAYER metal3 ;
      RECT 0.000 40.182 0.067 40.249 ;
    END
  END rd_out[17]
  PIN rd_out[18]
    DIRECTION OUTPUT ;
    USE SIGNAL ;
    SHAPE ABUTMENT ;
    PORT
      LAYER metal3 ;
      RECT 0.000 40.448 0.067 40.515 ;
    END
  END rd_out[18]
  PIN rd_out[19]
    DIRECTION OUTPUT ;
    USE SIGNAL ;
    SHAPE ABUTMENT ;
    PORT
      LAYER metal3 ;
      RECT 0.000 40.714 0.067 40.781 ;
    END
  END rd_out[19]
  PIN rd_out[20]
    DIRECTION OUTPUT ;
    USE SIGNAL ;
    SHAPE ABUTMENT ;
    PORT
      LAYER metal3 ;
      RECT 0.000 40.980 0.067 41.047 ;
    END
  END rd_out[20]
  PIN rd_out[21]
    DIRECTION OUTPUT ;
    USE SIGNAL ;
    SHAPE ABUTMENT ;
    PORT
      LAYER metal3 ;
      RECT 0.000 41.247 0.067 41.313 ;
    END
  END rd_out[21]
  PIN rd_out[22]
    DIRECTION OUTPUT ;
    USE SIGNAL ;
    SHAPE ABUTMENT ;
    PORT
      LAYER metal3 ;
      RECT 0.000 41.513 0.067 41.579 ;
    END
  END rd_out[22]
  PIN rd_out[23]
    DIRECTION OUTPUT ;
    USE SIGNAL ;
    SHAPE ABUTMENT ;
    PORT
      LAYER metal3 ;
      RECT 0.000 41.779 0.067 41.845 ;
    END
  END rd_out[23]
  PIN rd_out[24]
    DIRECTION OUTPUT ;
    USE SIGNAL ;
    SHAPE ABUTMENT ;
    PORT
      LAYER metal3 ;
      RECT 0.000 42.045 0.067 42.111 ;
    END
  END rd_out[24]
  PIN rd_out[25]
    DIRECTION OUTPUT ;
    USE SIGNAL ;
    SHAPE ABUTMENT ;
    PORT
      LAYER metal3 ;
      RECT 0.000 42.311 0.067 42.378 ;
    END
  END rd_out[25]
  PIN rd_out[26]
    DIRECTION OUTPUT ;
    USE SIGNAL ;
    SHAPE ABUTMENT ;
    PORT
      LAYER metal3 ;
      RECT 0.000 42.577 0.067 42.644 ;
    END
  END rd_out[26]
  PIN rd_out[27]
    DIRECTION OUTPUT ;
    USE SIGNAL ;
    SHAPE ABUTMENT ;
    PORT
      LAYER metal3 ;
      RECT 0.000 42.843 0.067 42.910 ;
    END
  END rd_out[27]
  PIN rd_out[28]
    DIRECTION OUTPUT ;
    USE SIGNAL ;
    SHAPE ABUTMENT ;
    PORT
      LAYER metal3 ;
      RECT 0.000 43.109 0.067 43.176 ;
    END
  END rd_out[28]
  PIN rd_out[29]
    DIRECTION OUTPUT ;
    USE SIGNAL ;
    SHAPE ABUTMENT ;
    PORT
      LAYER metal3 ;
      RECT 0.000 43.375 0.067 43.442 ;
    END
  END rd_out[29]
  PIN rd_out[30]
    DIRECTION OUTPUT ;
    USE SIGNAL ;
    SHAPE ABUTMENT ;
    PORT
      LAYER metal3 ;
      RECT 0.000 43.642 0.067 43.708 ;
    END
  END rd_out[30]
  PIN rd_out[31]
    DIRECTION OUTPUT ;
    USE SIGNAL ;
    SHAPE ABUTMENT ;
    PORT
      LAYER metal3 ;
      RECT 0.000 43.908 0.067 43.974 ;
    END
  END rd_out[31]
  PIN rd_out[32]
    DIRECTION OUTPUT ;
    USE SIGNAL ;
    SHAPE ABUTMENT ;
    PORT
      LAYER metal3 ;
      RECT 0.000 44.174 0.067 44.240 ;
    END
  END rd_out[32]
  PIN rd_out[33]
    DIRECTION OUTPUT ;
    USE SIGNAL ;
    SHAPE ABUTMENT ;
    PORT
      LAYER metal3 ;
      RECT 0.000 44.440 0.067 44.506 ;
    END
  END rd_out[33]
  PIN rd_out[34]
    DIRECTION OUTPUT ;
    USE SIGNAL ;
    SHAPE ABUTMENT ;
    PORT
      LAYER metal3 ;
      RECT 0.000 44.706 0.067 44.772 ;
    END
  END rd_out[34]
  PIN rd_out[35]
    DIRECTION OUTPUT ;
    USE SIGNAL ;
    SHAPE ABUTMENT ;
    PORT
      LAYER metal3 ;
      RECT 0.000 44.972 0.067 45.039 ;
    END
  END rd_out[35]
  PIN rd_out[36]
    DIRECTION OUTPUT ;
    USE SIGNAL ;
    SHAPE ABUTMENT ;
    PORT
      LAYER metal3 ;
      RECT 0.000 45.238 0.067 45.305 ;
    END
  END rd_out[36]
  PIN rd_out[37]
    DIRECTION OUTPUT ;
    USE SIGNAL ;
    SHAPE ABUTMENT ;
    PORT
      LAYER metal3 ;
      RECT 0.000 45.504 0.067 45.571 ;
    END
  END rd_out[37]
  PIN rd_out[38]
    DIRECTION OUTPUT ;
    USE SIGNAL ;
    SHAPE ABUTMENT ;
    PORT
      LAYER metal3 ;
      RECT 0.000 45.770 0.067 45.837 ;
    END
  END rd_out[38]
  PIN rd_out[39]
    DIRECTION OUTPUT ;
    USE SIGNAL ;
    SHAPE ABUTMENT ;
    PORT
      LAYER metal3 ;
      RECT 0.000 46.037 0.067 46.103 ;
    END
  END rd_out[39]
  PIN rd_out[40]
    DIRECTION OUTPUT ;
    USE SIGNAL ;
    SHAPE ABUTMENT ;
    PORT
      LAYER metal3 ;
      RECT 0.000 46.303 0.067 46.369 ;
    END
  END rd_out[40]
  PIN rd_out[41]
    DIRECTION OUTPUT ;
    USE SIGNAL ;
    SHAPE ABUTMENT ;
    PORT
      LAYER metal3 ;
      RECT 0.000 46.569 0.067 46.635 ;
    END
  END rd_out[41]
  PIN rd_out[42]
    DIRECTION OUTPUT ;
    USE SIGNAL ;
    SHAPE ABUTMENT ;
    PORT
      LAYER metal3 ;
      RECT 0.000 46.835 0.067 46.901 ;
    END
  END rd_out[42]
  PIN rd_out[43]
    DIRECTION OUTPUT ;
    USE SIGNAL ;
    SHAPE ABUTMENT ;
    PORT
      LAYER metal3 ;
      RECT 0.000 47.101 0.067 47.167 ;
    END
  END rd_out[43]
  PIN rd_out[44]
    DIRECTION OUTPUT ;
    USE SIGNAL ;
    SHAPE ABUTMENT ;
    PORT
      LAYER metal3 ;
      RECT 0.000 47.367 0.067 47.434 ;
    END
  END rd_out[44]
  PIN rd_out[45]
    DIRECTION OUTPUT ;
    USE SIGNAL ;
    SHAPE ABUTMENT ;
    PORT
      LAYER metal3 ;
      RECT 0.000 47.633 0.067 47.700 ;
    END
  END rd_out[45]
  PIN rd_out[46]
    DIRECTION OUTPUT ;
    USE SIGNAL ;
    SHAPE ABUTMENT ;
    PORT
      LAYER metal3 ;
      RECT 0.000 47.899 0.067 47.966 ;
    END
  END rd_out[46]
  PIN rd_out[47]
    DIRECTION OUTPUT ;
    USE SIGNAL ;
    SHAPE ABUTMENT ;
    PORT
      LAYER metal3 ;
      RECT 0.000 48.165 0.067 48.232 ;
    END
  END rd_out[47]
  PIN rd_out[48]
    DIRECTION OUTPUT ;
    USE SIGNAL ;
    SHAPE ABUTMENT ;
    PORT
      LAYER metal3 ;
      RECT 0.000 48.431 0.067 48.498 ;
    END
  END rd_out[48]
  PIN rd_out[49]
    DIRECTION OUTPUT ;
    USE SIGNAL ;
    SHAPE ABUTMENT ;
    PORT
      LAYER metal3 ;
      RECT 0.000 48.698 0.067 48.764 ;
    END
  END rd_out[49]
  PIN rd_out[50]
    DIRECTION OUTPUT ;
    USE SIGNAL ;
    SHAPE ABUTMENT ;
    PORT
      LAYER metal3 ;
      RECT 0.000 48.964 0.067 49.030 ;
    END
  END rd_out[50]
  PIN rd_out[51]
    DIRECTION OUTPUT ;
    USE SIGNAL ;
    SHAPE ABUTMENT ;
    PORT
      LAYER metal3 ;
      RECT 0.000 49.230 0.067 49.296 ;
    END
  END rd_out[51]
  PIN rd_out[52]
    DIRECTION OUTPUT ;
    USE SIGNAL ;
    SHAPE ABUTMENT ;
    PORT
      LAYER metal3 ;
      RECT 0.000 49.496 0.067 49.562 ;
    END
  END rd_out[52]
  PIN rd_out[53]
    DIRECTION OUTPUT ;
    USE SIGNAL ;
    SHAPE ABUTMENT ;
    PORT
      LAYER metal3 ;
      RECT 0.000 49.762 0.067 49.829 ;
    END
  END rd_out[53]
  PIN rd_out[54]
    DIRECTION OUTPUT ;
    USE SIGNAL ;
    SHAPE ABUTMENT ;
    PORT
      LAYER metal3 ;
      RECT 0.000 50.028 0.067 50.095 ;
    END
  END rd_out[54]
  PIN rd_out[55]
    DIRECTION OUTPUT ;
    USE SIGNAL ;
    SHAPE ABUTMENT ;
    PORT
      LAYER metal3 ;
      RECT 0.000 50.294 0.067 50.361 ;
    END
  END rd_out[55]
  PIN rd_out[56]
    DIRECTION OUTPUT ;
    USE SIGNAL ;
    SHAPE ABUTMENT ;
    PORT
      LAYER metal3 ;
      RECT 0.000 50.560 0.067 50.627 ;
    END
  END rd_out[56]
  PIN rd_out[57]
    DIRECTION OUTPUT ;
    USE SIGNAL ;
    SHAPE ABUTMENT ;
    PORT
      LAYER metal3 ;
      RECT 0.000 50.826 0.067 50.893 ;
    END
  END rd_out[57]
  PIN rd_out[58]
    DIRECTION OUTPUT ;
    USE SIGNAL ;
    SHAPE ABUTMENT ;
    PORT
      LAYER metal3 ;
      RECT 0.000 51.093 0.067 51.159 ;
    END
  END rd_out[58]
  PIN rd_out[59]
    DIRECTION OUTPUT ;
    USE SIGNAL ;
    SHAPE ABUTMENT ;
    PORT
      LAYER metal3 ;
      RECT 0.000 51.359 0.067 51.425 ;
    END
  END rd_out[59]
  PIN rd_out[60]
    DIRECTION OUTPUT ;
    USE SIGNAL ;
    SHAPE ABUTMENT ;
    PORT
      LAYER metal3 ;
      RECT 0.000 51.625 0.067 51.691 ;
    END
  END rd_out[60]
  PIN rd_out[61]
    DIRECTION OUTPUT ;
    USE SIGNAL ;
    SHAPE ABUTMENT ;
    PORT
      LAYER metal3 ;
      RECT 0.000 51.891 0.067 51.957 ;
    END
  END rd_out[61]
  PIN rd_out[62]
    DIRECTION OUTPUT ;
    USE SIGNAL ;
    SHAPE ABUTMENT ;
    PORT
      LAYER metal3 ;
      RECT 0.000 52.157 0.067 52.223 ;
    END
  END rd_out[62]
  PIN rd_out[63]
    DIRECTION OUTPUT ;
    USE SIGNAL ;
    SHAPE ABUTMENT ;
    PORT
      LAYER metal3 ;
      RECT 0.000 52.423 0.067 52.490 ;
    END
  END rd_out[63]
  PIN rd_out[64]
    DIRECTION OUTPUT ;
    USE SIGNAL ;
    SHAPE ABUTMENT ;
    PORT
      LAYER metal3 ;
      RECT 0.000 52.689 0.067 52.756 ;
    END
  END rd_out[64]
  PIN rd_out[65]
    DIRECTION OUTPUT ;
    USE SIGNAL ;
    SHAPE ABUTMENT ;
    PORT
      LAYER metal3 ;
      RECT 0.000 52.955 0.067 53.022 ;
    END
  END rd_out[65]
  PIN rd_out[66]
    DIRECTION OUTPUT ;
    USE SIGNAL ;
    SHAPE ABUTMENT ;
    PORT
      LAYER metal3 ;
      RECT 0.000 53.221 0.067 53.288 ;
    END
  END rd_out[66]
  PIN rd_out[67]
    DIRECTION OUTPUT ;
    USE SIGNAL ;
    SHAPE ABUTMENT ;
    PORT
      LAYER metal3 ;
      RECT 0.000 53.487 0.067 53.554 ;
    END
  END rd_out[67]
  PIN rd_out[68]
    DIRECTION OUTPUT ;
    USE SIGNAL ;
    SHAPE ABUTMENT ;
    PORT
      LAYER metal3 ;
      RECT 0.000 53.754 0.067 53.820 ;
    END
  END rd_out[68]
  PIN rd_out[69]
    DIRECTION OUTPUT ;
    USE SIGNAL ;
    SHAPE ABUTMENT ;
    PORT
      LAYER metal3 ;
      RECT 0.000 54.020 0.067 54.086 ;
    END
  END rd_out[69]
  PIN rd_out[70]
    DIRECTION OUTPUT ;
    USE SIGNAL ;
    SHAPE ABUTMENT ;
    PORT
      LAYER metal3 ;
      RECT 0.000 54.286 0.067 54.352 ;
    END
  END rd_out[70]
  PIN rd_out[71]
    DIRECTION OUTPUT ;
    USE SIGNAL ;
    SHAPE ABUTMENT ;
    PORT
      LAYER metal3 ;
      RECT 0.000 54.552 0.067 54.618 ;
    END
  END rd_out[71]
  PIN rd_out[72]
    DIRECTION OUTPUT ;
    USE SIGNAL ;
    SHAPE ABUTMENT ;
    PORT
      LAYER metal3 ;
      RECT 0.000 54.818 0.067 54.885 ;
    END
  END rd_out[72]
  PIN rd_out[73]
    DIRECTION OUTPUT ;
    USE SIGNAL ;
    SHAPE ABUTMENT ;
    PORT
      LAYER metal3 ;
      RECT 0.000 55.084 0.067 55.151 ;
    END
  END rd_out[73]
  PIN rd_out[74]
    DIRECTION OUTPUT ;
    USE SIGNAL ;
    SHAPE ABUTMENT ;
    PORT
      LAYER metal3 ;
      RECT 0.000 55.350 0.067 55.417 ;
    END
  END rd_out[74]
  PIN rd_out[75]
    DIRECTION OUTPUT ;
    USE SIGNAL ;
    SHAPE ABUTMENT ;
    PORT
      LAYER metal3 ;
      RECT 0.000 55.616 0.067 55.683 ;
    END
  END rd_out[75]
  PIN rd_out[76]
    DIRECTION OUTPUT ;
    USE SIGNAL ;
    SHAPE ABUTMENT ;
    PORT
      LAYER metal3 ;
      RECT 0.000 55.882 0.067 55.949 ;
    END
  END rd_out[76]
  PIN rd_out[77]
    DIRECTION OUTPUT ;
    USE SIGNAL ;
    SHAPE ABUTMENT ;
    PORT
      LAYER metal3 ;
      RECT 0.000 56.149 0.067 56.215 ;
    END
  END rd_out[77]
  PIN rd_out[78]
    DIRECTION OUTPUT ;
    USE SIGNAL ;
    SHAPE ABUTMENT ;
    PORT
      LAYER metal3 ;
      RECT 0.000 56.415 0.067 56.481 ;
    END
  END rd_out[78]
  PIN rd_out[79]
    DIRECTION OUTPUT ;
    USE SIGNAL ;
    SHAPE ABUTMENT ;
    PORT
      LAYER metal3 ;
      RECT 0.000 56.681 0.067 56.747 ;
    END
  END rd_out[79]
  PIN rd_out[80]
    DIRECTION OUTPUT ;
    USE SIGNAL ;
    SHAPE ABUTMENT ;
    PORT
      LAYER metal3 ;
      RECT 0.000 56.947 0.067 57.013 ;
    END
  END rd_out[80]
  PIN rd_out[81]
    DIRECTION OUTPUT ;
    USE SIGNAL ;
    SHAPE ABUTMENT ;
    PORT
      LAYER metal3 ;
      RECT 0.000 57.213 0.067 57.280 ;
    END
  END rd_out[81]
  PIN rd_out[82]
    DIRECTION OUTPUT ;
    USE SIGNAL ;
    SHAPE ABUTMENT ;
    PORT
      LAYER metal3 ;
      RECT 0.000 57.479 0.067 57.546 ;
    END
  END rd_out[82]
  PIN rd_out[83]
    DIRECTION OUTPUT ;
    USE SIGNAL ;
    SHAPE ABUTMENT ;
    PORT
      LAYER metal3 ;
      RECT 0.000 57.745 0.067 57.812 ;
    END
  END rd_out[83]
  PIN rd_out[84]
    DIRECTION OUTPUT ;
    USE SIGNAL ;
    SHAPE ABUTMENT ;
    PORT
      LAYER metal3 ;
      RECT 0.000 58.011 0.067 58.078 ;
    END
  END rd_out[84]
  PIN rd_out[85]
    DIRECTION OUTPUT ;
    USE SIGNAL ;
    SHAPE ABUTMENT ;
    PORT
      LAYER metal3 ;
      RECT 0.000 58.277 0.067 58.344 ;
    END
  END rd_out[85]
  PIN rd_out[86]
    DIRECTION OUTPUT ;
    USE SIGNAL ;
    SHAPE ABUTMENT ;
    PORT
      LAYER metal3 ;
      RECT 0.000 58.544 0.067 58.610 ;
    END
  END rd_out[86]
  PIN rd_out[87]
    DIRECTION OUTPUT ;
    USE SIGNAL ;
    SHAPE ABUTMENT ;
    PORT
      LAYER metal3 ;
      RECT 0.000 58.810 0.067 58.876 ;
    END
  END rd_out[87]
  PIN rd_out[88]
    DIRECTION OUTPUT ;
    USE SIGNAL ;
    SHAPE ABUTMENT ;
    PORT
      LAYER metal3 ;
      RECT 0.000 59.076 0.067 59.142 ;
    END
  END rd_out[88]
  PIN rd_out[89]
    DIRECTION OUTPUT ;
    USE SIGNAL ;
    SHAPE ABUTMENT ;
    PORT
      LAYER metal3 ;
      RECT 0.000 59.342 0.067 59.408 ;
    END
  END rd_out[89]
  PIN rd_out[90]
    DIRECTION OUTPUT ;
    USE SIGNAL ;
    SHAPE ABUTMENT ;
    PORT
      LAYER metal3 ;
      RECT 0.000 59.608 0.067 59.674 ;
    END
  END rd_out[90]
  PIN rd_out[91]
    DIRECTION OUTPUT ;
    USE SIGNAL ;
    SHAPE ABUTMENT ;
    PORT
      LAYER metal3 ;
      RECT 0.000 59.874 0.067 59.941 ;
    END
  END rd_out[91]
  PIN rd_out[92]
    DIRECTION OUTPUT ;
    USE SIGNAL ;
    SHAPE ABUTMENT ;
    PORT
      LAYER metal3 ;
      RECT 0.000 60.140 0.067 60.207 ;
    END
  END rd_out[92]
  PIN rd_out[93]
    DIRECTION OUTPUT ;
    USE SIGNAL ;
    SHAPE ABUTMENT ;
    PORT
      LAYER metal3 ;
      RECT 0.000 60.406 0.067 60.473 ;
    END
  END rd_out[93]
  PIN rd_out[94]
    DIRECTION OUTPUT ;
    USE SIGNAL ;
    SHAPE ABUTMENT ;
    PORT
      LAYER metal3 ;
      RECT 0.000 60.672 0.067 60.739 ;
    END
  END rd_out[94]
  PIN rd_out[95]
    DIRECTION OUTPUT ;
    USE SIGNAL ;
    SHAPE ABUTMENT ;
    PORT
      LAYER metal3 ;
      RECT 0.000 60.938 0.067 61.005 ;
    END
  END rd_out[95]
  PIN rd_out[96]
    DIRECTION OUTPUT ;
    USE SIGNAL ;
    SHAPE ABUTMENT ;
    PORT
      LAYER metal3 ;
      RECT 0.000 61.205 0.067 61.271 ;
    END
  END rd_out[96]
  PIN rd_out[97]
    DIRECTION OUTPUT ;
    USE SIGNAL ;
    SHAPE ABUTMENT ;
    PORT
      LAYER metal3 ;
      RECT 0.000 61.471 0.067 61.537 ;
    END
  END rd_out[97]
  PIN rd_out[98]
    DIRECTION OUTPUT ;
    USE SIGNAL ;
    SHAPE ABUTMENT ;
    PORT
      LAYER metal3 ;
      RECT 0.000 61.737 0.067 61.803 ;
    END
  END rd_out[98]
  PIN rd_out[99]
    DIRECTION OUTPUT ;
    USE SIGNAL ;
    SHAPE ABUTMENT ;
    PORT
      LAYER metal3 ;
      RECT 0.000 62.003 0.067 62.069 ;
    END
  END rd_out[99]
  PIN rd_out[100]
    DIRECTION OUTPUT ;
    USE SIGNAL ;
    SHAPE ABUTMENT ;
    PORT
      LAYER metal3 ;
      RECT 0.000 62.269 0.067 62.336 ;
    END
  END rd_out[100]
  PIN rd_out[101]
    DIRECTION OUTPUT ;
    USE SIGNAL ;
    SHAPE ABUTMENT ;
    PORT
      LAYER metal3 ;
      RECT 0.000 62.535 0.067 62.602 ;
    END
  END rd_out[101]
  PIN rd_out[102]
    DIRECTION OUTPUT ;
    USE SIGNAL ;
    SHAPE ABUTMENT ;
    PORT
      LAYER metal3 ;
      RECT 0.000 62.801 0.067 62.868 ;
    END
  END rd_out[102]
  PIN rd_out[103]
    DIRECTION OUTPUT ;
    USE SIGNAL ;
    SHAPE ABUTMENT ;
    PORT
      LAYER metal3 ;
      RECT 0.000 63.067 0.067 63.134 ;
    END
  END rd_out[103]
  PIN rd_out[104]
    DIRECTION OUTPUT ;
    USE SIGNAL ;
    SHAPE ABUTMENT ;
    PORT
      LAYER metal3 ;
      RECT 0.000 63.333 0.067 63.400 ;
    END
  END rd_out[104]
  PIN rd_out[105]
    DIRECTION OUTPUT ;
    USE SIGNAL ;
    SHAPE ABUTMENT ;
    PORT
      LAYER metal3 ;
      RECT 0.000 63.600 0.067 63.666 ;
    END
  END rd_out[105]
  PIN rd_out[106]
    DIRECTION OUTPUT ;
    USE SIGNAL ;
    SHAPE ABUTMENT ;
    PORT
      LAYER metal3 ;
      RECT 0.000 63.866 0.067 63.932 ;
    END
  END rd_out[106]
  PIN rd_out[107]
    DIRECTION OUTPUT ;
    USE SIGNAL ;
    SHAPE ABUTMENT ;
    PORT
      LAYER metal3 ;
      RECT 0.000 64.132 0.067 64.198 ;
    END
  END rd_out[107]
  PIN rd_out[108]
    DIRECTION OUTPUT ;
    USE SIGNAL ;
    SHAPE ABUTMENT ;
    PORT
      LAYER metal3 ;
      RECT 0.000 64.398 0.067 64.464 ;
    END
  END rd_out[108]
  PIN rd_out[109]
    DIRECTION OUTPUT ;
    USE SIGNAL ;
    SHAPE ABUTMENT ;
    PORT
      LAYER metal3 ;
      RECT 0.000 64.664 0.067 64.731 ;
    END
  END rd_out[109]
  PIN rd_out[110]
    DIRECTION OUTPUT ;
    USE SIGNAL ;
    SHAPE ABUTMENT ;
    PORT
      LAYER metal3 ;
      RECT 0.000 64.930 0.067 64.997 ;
    END
  END rd_out[110]
  PIN rd_out[111]
    DIRECTION OUTPUT ;
    USE SIGNAL ;
    SHAPE ABUTMENT ;
    PORT
      LAYER metal3 ;
      RECT 0.000 65.196 0.067 65.263 ;
    END
  END rd_out[111]
  PIN rd_out[112]
    DIRECTION OUTPUT ;
    USE SIGNAL ;
    SHAPE ABUTMENT ;
    PORT
      LAYER metal3 ;
      RECT 0.000 65.462 0.067 65.529 ;
    END
  END rd_out[112]
  PIN rd_out[113]
    DIRECTION OUTPUT ;
    USE SIGNAL ;
    SHAPE ABUTMENT ;
    PORT
      LAYER metal3 ;
      RECT 0.000 65.728 0.067 65.795 ;
    END
  END rd_out[113]
  PIN rd_out[114]
    DIRECTION OUTPUT ;
    USE SIGNAL ;
    SHAPE ABUTMENT ;
    PORT
      LAYER metal3 ;
      RECT 0.000 65.995 0.067 66.061 ;
    END
  END rd_out[114]
  PIN rd_out[115]
    DIRECTION OUTPUT ;
    USE SIGNAL ;
    SHAPE ABUTMENT ;
    PORT
      LAYER metal3 ;
      RECT 0.000 66.261 0.067 66.327 ;
    END
  END rd_out[115]
  PIN rd_out[116]
    DIRECTION OUTPUT ;
    USE SIGNAL ;
    SHAPE ABUTMENT ;
    PORT
      LAYER metal3 ;
      RECT 0.000 66.527 0.067 66.593 ;
    END
  END rd_out[116]
  PIN rd_out[117]
    DIRECTION OUTPUT ;
    USE SIGNAL ;
    SHAPE ABUTMENT ;
    PORT
      LAYER metal3 ;
      RECT 0.000 66.793 0.067 66.859 ;
    END
  END rd_out[117]
  PIN rd_out[118]
    DIRECTION OUTPUT ;
    USE SIGNAL ;
    SHAPE ABUTMENT ;
    PORT
      LAYER metal3 ;
      RECT 0.000 67.059 0.067 67.125 ;
    END
  END rd_out[118]
  PIN rd_out[119]
    DIRECTION OUTPUT ;
    USE SIGNAL ;
    SHAPE ABUTMENT ;
    PORT
      LAYER metal3 ;
      RECT 0.000 67.325 0.067 67.392 ;
    END
  END rd_out[119]
  PIN rd_out[120]
    DIRECTION OUTPUT ;
    USE SIGNAL ;
    SHAPE ABUTMENT ;
    PORT
      LAYER metal3 ;
      RECT 0.000 67.591 0.067 67.658 ;
    END
  END rd_out[120]
  PIN rd_out[121]
    DIRECTION OUTPUT ;
    USE SIGNAL ;
    SHAPE ABUTMENT ;
    PORT
      LAYER metal3 ;
      RECT 0.000 67.857 0.067 67.924 ;
    END
  END rd_out[121]
  PIN rd_out[122]
    DIRECTION OUTPUT ;
    USE SIGNAL ;
    SHAPE ABUTMENT ;
    PORT
      LAYER metal3 ;
      RECT 0.000 68.123 0.067 68.190 ;
    END
  END rd_out[122]
  PIN rd_out[123]
    DIRECTION OUTPUT ;
    USE SIGNAL ;
    SHAPE ABUTMENT ;
    PORT
      LAYER metal3 ;
      RECT 0.000 68.389 0.067 68.456 ;
    END
  END rd_out[123]
  PIN wd_in[0]
    DIRECTION INPUT ;
    USE SIGNAL ;
    SHAPE ABUTMENT ;
    PORT
      LAYER metal3 ;
      RECT 0.000 68.656 0.067 68.722 ;
    END
  END wd_in[0]
  PIN wd_in[1]
    DIRECTION INPUT ;
    USE SIGNAL ;
    SHAPE ABUTMENT ;
    PORT
      LAYER metal3 ;
      RECT 0.000 68.922 0.067 68.988 ;
    END
  END wd_in[1]
  PIN wd_in[2]
    DIRECTION INPUT ;
    USE SIGNAL ;
    SHAPE ABUTMENT ;
    PORT
      LAYER metal3 ;
      RECT 0.000 69.188 0.067 69.254 ;
    END
  END wd_in[2]
  PIN wd_in[3]
    DIRECTION INPUT ;
    USE SIGNAL ;
    SHAPE ABUTMENT ;
    PORT
      LAYER metal3 ;
      RECT 0.000 69.454 0.067 69.520 ;
    END
  END wd_in[3]
  PIN wd_in[4]
    DIRECTION INPUT ;
    USE SIGNAL ;
    SHAPE ABUTMENT ;
    PORT
      LAYER metal3 ;
      RECT 0.000 69.720 0.067 69.787 ;
    END
  END wd_in[4]
  PIN wd_in[5]
    DIRECTION INPUT ;
    USE SIGNAL ;
    SHAPE ABUTMENT ;
    PORT
      LAYER metal3 ;
      RECT 0.000 69.986 0.067 70.053 ;
    END
  END wd_in[5]
  PIN wd_in[6]
    DIRECTION INPUT ;
    USE SIGNAL ;
    SHAPE ABUTMENT ;
    PORT
      LAYER metal3 ;
      RECT 0.000 70.252 0.067 70.319 ;
    END
  END wd_in[6]
  PIN wd_in[7]
    DIRECTION INPUT ;
    USE SIGNAL ;
    SHAPE ABUTMENT ;
    PORT
      LAYER metal3 ;
      RECT 0.000 70.518 0.067 70.585 ;
    END
  END wd_in[7]
  PIN wd_in[8]
    DIRECTION INPUT ;
    USE SIGNAL ;
    SHAPE ABUTMENT ;
    PORT
      LAYER metal3 ;
      RECT 0.000 70.784 0.067 70.851 ;
    END
  END wd_in[8]
  PIN wd_in[9]
    DIRECTION INPUT ;
    USE SIGNAL ;
    SHAPE ABUTMENT ;
    PORT
      LAYER metal3 ;
      RECT 0.000 71.051 0.067 71.117 ;
    END
  END wd_in[9]
  PIN wd_in[10]
    DIRECTION INPUT ;
    USE SIGNAL ;
    SHAPE ABUTMENT ;
    PORT
      LAYER metal3 ;
      RECT 0.000 71.317 0.067 71.383 ;
    END
  END wd_in[10]
  PIN wd_in[11]
    DIRECTION INPUT ;
    USE SIGNAL ;
    SHAPE ABUTMENT ;
    PORT
      LAYER metal3 ;
      RECT 0.000 71.583 0.067 71.649 ;
    END
  END wd_in[11]
  PIN wd_in[12]
    DIRECTION INPUT ;
    USE SIGNAL ;
    SHAPE ABUTMENT ;
    PORT
      LAYER metal3 ;
      RECT 0.000 71.849 0.067 71.915 ;
    END
  END wd_in[12]
  PIN wd_in[13]
    DIRECTION INPUT ;
    USE SIGNAL ;
    SHAPE ABUTMENT ;
    PORT
      LAYER metal3 ;
      RECT 0.000 72.115 0.067 72.182 ;
    END
  END wd_in[13]
  PIN wd_in[14]
    DIRECTION INPUT ;
    USE SIGNAL ;
    SHAPE ABUTMENT ;
    PORT
      LAYER metal3 ;
      RECT 0.000 72.381 0.067 72.448 ;
    END
  END wd_in[14]
  PIN wd_in[15]
    DIRECTION INPUT ;
    USE SIGNAL ;
    SHAPE ABUTMENT ;
    PORT
      LAYER metal3 ;
      RECT 0.000 72.647 0.067 72.714 ;
    END
  END wd_in[15]
  PIN wd_in[16]
    DIRECTION INPUT ;
    USE SIGNAL ;
    SHAPE ABUTMENT ;
    PORT
      LAYER metal3 ;
      RECT 0.000 72.913 0.067 72.980 ;
    END
  END wd_in[16]
  PIN wd_in[17]
    DIRECTION INPUT ;
    USE SIGNAL ;
    SHAPE ABUTMENT ;
    PORT
      LAYER metal3 ;
      RECT 0.000 73.179 0.067 73.246 ;
    END
  END wd_in[17]
  PIN wd_in[18]
    DIRECTION INPUT ;
    USE SIGNAL ;
    SHAPE ABUTMENT ;
    PORT
      LAYER metal3 ;
      RECT 0.000 73.446 0.067 73.512 ;
    END
  END wd_in[18]
  PIN wd_in[19]
    DIRECTION INPUT ;
    USE SIGNAL ;
    SHAPE ABUTMENT ;
    PORT
      LAYER metal3 ;
      RECT 0.000 73.712 0.067 73.778 ;
    END
  END wd_in[19]
  PIN wd_in[20]
    DIRECTION INPUT ;
    USE SIGNAL ;
    SHAPE ABUTMENT ;
    PORT
      LAYER metal3 ;
      RECT 0.000 73.978 0.067 74.044 ;
    END
  END wd_in[20]
  PIN wd_in[21]
    DIRECTION INPUT ;
    USE SIGNAL ;
    SHAPE ABUTMENT ;
    PORT
      LAYER metal3 ;
      RECT 0.000 74.244 0.067 74.310 ;
    END
  END wd_in[21]
  PIN wd_in[22]
    DIRECTION INPUT ;
    USE SIGNAL ;
    SHAPE ABUTMENT ;
    PORT
      LAYER metal3 ;
      RECT 0.000 74.510 0.067 74.576 ;
    END
  END wd_in[22]
  PIN wd_in[23]
    DIRECTION INPUT ;
    USE SIGNAL ;
    SHAPE ABUTMENT ;
    PORT
      LAYER metal3 ;
      RECT 0.000 74.776 0.067 74.843 ;
    END
  END wd_in[23]
  PIN wd_in[24]
    DIRECTION INPUT ;
    USE SIGNAL ;
    SHAPE ABUTMENT ;
    PORT
      LAYER metal3 ;
      RECT 0.000 75.042 0.067 75.109 ;
    END
  END wd_in[24]
  PIN wd_in[25]
    DIRECTION INPUT ;
    USE SIGNAL ;
    SHAPE ABUTMENT ;
    PORT
      LAYER metal3 ;
      RECT 0.000 75.308 0.067 75.375 ;
    END
  END wd_in[25]
  PIN wd_in[26]
    DIRECTION INPUT ;
    USE SIGNAL ;
    SHAPE ABUTMENT ;
    PORT
      LAYER metal3 ;
      RECT 0.000 75.574 0.067 75.641 ;
    END
  END wd_in[26]
  PIN wd_in[27]
    DIRECTION INPUT ;
    USE SIGNAL ;
    SHAPE ABUTMENT ;
    PORT
      LAYER metal3 ;
      RECT 0.000 75.840 0.067 75.907 ;
    END
  END wd_in[27]
  PIN wd_in[28]
    DIRECTION INPUT ;
    USE SIGNAL ;
    SHAPE ABUTMENT ;
    PORT
      LAYER metal3 ;
      RECT 0.000 76.107 0.067 76.173 ;
    END
  END wd_in[28]
  PIN wd_in[29]
    DIRECTION INPUT ;
    USE SIGNAL ;
    SHAPE ABUTMENT ;
    PORT
      LAYER metal3 ;
      RECT 0.000 76.373 0.067 76.439 ;
    END
  END wd_in[29]
  PIN wd_in[30]
    DIRECTION INPUT ;
    USE SIGNAL ;
    SHAPE ABUTMENT ;
    PORT
      LAYER metal3 ;
      RECT 0.000 76.639 0.067 76.705 ;
    END
  END wd_in[30]
  PIN wd_in[31]
    DIRECTION INPUT ;
    USE SIGNAL ;
    SHAPE ABUTMENT ;
    PORT
      LAYER metal3 ;
      RECT 0.000 76.905 0.067 76.971 ;
    END
  END wd_in[31]
  PIN wd_in[32]
    DIRECTION INPUT ;
    USE SIGNAL ;
    SHAPE ABUTMENT ;
    PORT
      LAYER metal3 ;
      RECT 0.000 77.171 0.067 77.238 ;
    END
  END wd_in[32]
  PIN wd_in[33]
    DIRECTION INPUT ;
    USE SIGNAL ;
    SHAPE ABUTMENT ;
    PORT
      LAYER metal3 ;
      RECT 0.000 77.437 0.067 77.504 ;
    END
  END wd_in[33]
  PIN wd_in[34]
    DIRECTION INPUT ;
    USE SIGNAL ;
    SHAPE ABUTMENT ;
    PORT
      LAYER metal3 ;
      RECT 0.000 77.703 0.067 77.770 ;
    END
  END wd_in[34]
  PIN wd_in[35]
    DIRECTION INPUT ;
    USE SIGNAL ;
    SHAPE ABUTMENT ;
    PORT
      LAYER metal3 ;
      RECT 0.000 77.969 0.067 78.036 ;
    END
  END wd_in[35]
  PIN wd_in[36]
    DIRECTION INPUT ;
    USE SIGNAL ;
    SHAPE ABUTMENT ;
    PORT
      LAYER metal3 ;
      RECT 0.000 78.235 0.067 78.302 ;
    END
  END wd_in[36]
  PIN wd_in[37]
    DIRECTION INPUT ;
    USE SIGNAL ;
    SHAPE ABUTMENT ;
    PORT
      LAYER metal3 ;
      RECT 0.000 78.502 0.067 78.568 ;
    END
  END wd_in[37]
  PIN wd_in[38]
    DIRECTION INPUT ;
    USE SIGNAL ;
    SHAPE ABUTMENT ;
    PORT
      LAYER metal3 ;
      RECT 0.000 78.768 0.067 78.834 ;
    END
  END wd_in[38]
  PIN wd_in[39]
    DIRECTION INPUT ;
    USE SIGNAL ;
    SHAPE ABUTMENT ;
    PORT
      LAYER metal3 ;
      RECT 0.000 79.034 0.067 79.100 ;
    END
  END wd_in[39]
  PIN wd_in[40]
    DIRECTION INPUT ;
    USE SIGNAL ;
    SHAPE ABUTMENT ;
    PORT
      LAYER metal3 ;
      RECT 0.000 79.300 0.067 79.366 ;
    END
  END wd_in[40]
  PIN wd_in[41]
    DIRECTION INPUT ;
    USE SIGNAL ;
    SHAPE ABUTMENT ;
    PORT
      LAYER metal3 ;
      RECT 0.000 79.566 0.067 79.633 ;
    END
  END wd_in[41]
  PIN wd_in[42]
    DIRECTION INPUT ;
    USE SIGNAL ;
    SHAPE ABUTMENT ;
    PORT
      LAYER metal3 ;
      RECT 0.000 79.832 0.067 79.899 ;
    END
  END wd_in[42]
  PIN wd_in[43]
    DIRECTION INPUT ;
    USE SIGNAL ;
    SHAPE ABUTMENT ;
    PORT
      LAYER metal3 ;
      RECT 0.000 80.098 0.067 80.165 ;
    END
  END wd_in[43]
  PIN wd_in[44]
    DIRECTION INPUT ;
    USE SIGNAL ;
    SHAPE ABUTMENT ;
    PORT
      LAYER metal3 ;
      RECT 0.000 80.364 0.067 80.431 ;
    END
  END wd_in[44]
  PIN wd_in[45]
    DIRECTION INPUT ;
    USE SIGNAL ;
    SHAPE ABUTMENT ;
    PORT
      LAYER metal3 ;
      RECT 0.000 80.630 0.067 80.697 ;
    END
  END wd_in[45]
  PIN wd_in[46]
    DIRECTION INPUT ;
    USE SIGNAL ;
    SHAPE ABUTMENT ;
    PORT
      LAYER metal3 ;
      RECT 0.000 80.897 0.067 80.963 ;
    END
  END wd_in[46]
  PIN wd_in[47]
    DIRECTION INPUT ;
    USE SIGNAL ;
    SHAPE ABUTMENT ;
    PORT
      LAYER metal3 ;
      RECT 0.000 81.163 0.067 81.229 ;
    END
  END wd_in[47]
  PIN wd_in[48]
    DIRECTION INPUT ;
    USE SIGNAL ;
    SHAPE ABUTMENT ;
    PORT
      LAYER metal3 ;
      RECT 0.000 81.429 0.067 81.495 ;
    END
  END wd_in[48]
  PIN wd_in[49]
    DIRECTION INPUT ;
    USE SIGNAL ;
    SHAPE ABUTMENT ;
    PORT
      LAYER metal3 ;
      RECT 0.000 81.695 0.067 81.761 ;
    END
  END wd_in[49]
  PIN wd_in[50]
    DIRECTION INPUT ;
    USE SIGNAL ;
    SHAPE ABUTMENT ;
    PORT
      LAYER metal3 ;
      RECT 0.000 81.961 0.067 82.027 ;
    END
  END wd_in[50]
  PIN wd_in[51]
    DIRECTION INPUT ;
    USE SIGNAL ;
    SHAPE ABUTMENT ;
    PORT
      LAYER metal3 ;
      RECT 0.000 82.227 0.067 82.294 ;
    END
  END wd_in[51]
  PIN wd_in[52]
    DIRECTION INPUT ;
    USE SIGNAL ;
    SHAPE ABUTMENT ;
    PORT
      LAYER metal3 ;
      RECT 0.000 82.493 0.067 82.560 ;
    END
  END wd_in[52]
  PIN wd_in[53]
    DIRECTION INPUT ;
    USE SIGNAL ;
    SHAPE ABUTMENT ;
    PORT
      LAYER metal3 ;
      RECT 0.000 82.759 0.067 82.826 ;
    END
  END wd_in[53]
  PIN wd_in[54]
    DIRECTION INPUT ;
    USE SIGNAL ;
    SHAPE ABUTMENT ;
    PORT
      LAYER metal3 ;
      RECT 0.000 83.025 0.067 83.092 ;
    END
  END wd_in[54]
  PIN wd_in[55]
    DIRECTION INPUT ;
    USE SIGNAL ;
    SHAPE ABUTMENT ;
    PORT
      LAYER metal3 ;
      RECT 0.000 83.291 0.067 83.358 ;
    END
  END wd_in[55]
  PIN wd_in[56]
    DIRECTION INPUT ;
    USE SIGNAL ;
    SHAPE ABUTMENT ;
    PORT
      LAYER metal3 ;
      RECT 0.000 83.558 0.067 83.624 ;
    END
  END wd_in[56]
  PIN wd_in[57]
    DIRECTION INPUT ;
    USE SIGNAL ;
    SHAPE ABUTMENT ;
    PORT
      LAYER metal3 ;
      RECT 0.000 83.824 0.067 83.890 ;
    END
  END wd_in[57]
  PIN wd_in[58]
    DIRECTION INPUT ;
    USE SIGNAL ;
    SHAPE ABUTMENT ;
    PORT
      LAYER metal3 ;
      RECT 0.000 84.090 0.067 84.156 ;
    END
  END wd_in[58]
  PIN wd_in[59]
    DIRECTION INPUT ;
    USE SIGNAL ;
    SHAPE ABUTMENT ;
    PORT
      LAYER metal3 ;
      RECT 0.000 84.356 0.067 84.422 ;
    END
  END wd_in[59]
  PIN wd_in[60]
    DIRECTION INPUT ;
    USE SIGNAL ;
    SHAPE ABUTMENT ;
    PORT
      LAYER metal3 ;
      RECT 0.000 84.622 0.067 84.689 ;
    END
  END wd_in[60]
  PIN wd_in[61]
    DIRECTION INPUT ;
    USE SIGNAL ;
    SHAPE ABUTMENT ;
    PORT
      LAYER metal3 ;
      RECT 0.000 84.888 0.067 84.955 ;
    END
  END wd_in[61]
  PIN wd_in[62]
    DIRECTION INPUT ;
    USE SIGNAL ;
    SHAPE ABUTMENT ;
    PORT
      LAYER metal3 ;
      RECT 0.000 85.154 0.067 85.221 ;
    END
  END wd_in[62]
  PIN wd_in[63]
    DIRECTION INPUT ;
    USE SIGNAL ;
    SHAPE ABUTMENT ;
    PORT
      LAYER metal3 ;
      RECT 0.000 85.420 0.067 85.487 ;
    END
  END wd_in[63]
  PIN wd_in[64]
    DIRECTION INPUT ;
    USE SIGNAL ;
    SHAPE ABUTMENT ;
    PORT
      LAYER metal3 ;
      RECT 0.000 85.686 0.067 85.753 ;
    END
  END wd_in[64]
  PIN wd_in[65]
    DIRECTION INPUT ;
    USE SIGNAL ;
    SHAPE ABUTMENT ;
    PORT
      LAYER metal3 ;
      RECT 0.000 85.953 0.067 86.019 ;
    END
  END wd_in[65]
  PIN wd_in[66]
    DIRECTION INPUT ;
    USE SIGNAL ;
    SHAPE ABUTMENT ;
    PORT
      LAYER metal3 ;
      RECT 0.000 86.219 0.067 86.285 ;
    END
  END wd_in[66]
  PIN wd_in[67]
    DIRECTION INPUT ;
    USE SIGNAL ;
    SHAPE ABUTMENT ;
    PORT
      LAYER metal3 ;
      RECT 0.000 86.485 0.067 86.551 ;
    END
  END wd_in[67]
  PIN wd_in[68]
    DIRECTION INPUT ;
    USE SIGNAL ;
    SHAPE ABUTMENT ;
    PORT
      LAYER metal3 ;
      RECT 0.000 86.751 0.067 86.817 ;
    END
  END wd_in[68]
  PIN wd_in[69]
    DIRECTION INPUT ;
    USE SIGNAL ;
    SHAPE ABUTMENT ;
    PORT
      LAYER metal3 ;
      RECT 0.000 87.017 0.067 87.083 ;
    END
  END wd_in[69]
  PIN wd_in[70]
    DIRECTION INPUT ;
    USE SIGNAL ;
    SHAPE ABUTMENT ;
    PORT
      LAYER metal3 ;
      RECT 0.000 87.283 0.067 87.350 ;
    END
  END wd_in[70]
  PIN wd_in[71]
    DIRECTION INPUT ;
    USE SIGNAL ;
    SHAPE ABUTMENT ;
    PORT
      LAYER metal3 ;
      RECT 0.000 87.549 0.067 87.616 ;
    END
  END wd_in[71]
  PIN wd_in[72]
    DIRECTION INPUT ;
    USE SIGNAL ;
    SHAPE ABUTMENT ;
    PORT
      LAYER metal3 ;
      RECT 0.000 87.815 0.067 87.882 ;
    END
  END wd_in[72]
  PIN wd_in[73]
    DIRECTION INPUT ;
    USE SIGNAL ;
    SHAPE ABUTMENT ;
    PORT
      LAYER metal3 ;
      RECT 0.000 88.081 0.067 88.148 ;
    END
  END wd_in[73]
  PIN wd_in[74]
    DIRECTION INPUT ;
    USE SIGNAL ;
    SHAPE ABUTMENT ;
    PORT
      LAYER metal3 ;
      RECT 0.000 88.348 0.067 88.414 ;
    END
  END wd_in[74]
  PIN wd_in[75]
    DIRECTION INPUT ;
    USE SIGNAL ;
    SHAPE ABUTMENT ;
    PORT
      LAYER metal3 ;
      RECT 0.000 88.614 0.067 88.680 ;
    END
  END wd_in[75]
  PIN wd_in[76]
    DIRECTION INPUT ;
    USE SIGNAL ;
    SHAPE ABUTMENT ;
    PORT
      LAYER metal3 ;
      RECT 0.000 88.880 0.067 88.946 ;
    END
  END wd_in[76]
  PIN wd_in[77]
    DIRECTION INPUT ;
    USE SIGNAL ;
    SHAPE ABUTMENT ;
    PORT
      LAYER metal3 ;
      RECT 0.000 89.146 0.067 89.212 ;
    END
  END wd_in[77]
  PIN wd_in[78]
    DIRECTION INPUT ;
    USE SIGNAL ;
    SHAPE ABUTMENT ;
    PORT
      LAYER metal3 ;
      RECT 0.000 89.412 0.067 89.478 ;
    END
  END wd_in[78]
  PIN wd_in[79]
    DIRECTION INPUT ;
    USE SIGNAL ;
    SHAPE ABUTMENT ;
    PORT
      LAYER metal3 ;
      RECT 0.000 89.678 0.067 89.745 ;
    END
  END wd_in[79]
  PIN wd_in[80]
    DIRECTION INPUT ;
    USE SIGNAL ;
    SHAPE ABUTMENT ;
    PORT
      LAYER metal3 ;
      RECT 0.000 89.944 0.067 90.011 ;
    END
  END wd_in[80]
  PIN wd_in[81]
    DIRECTION INPUT ;
    USE SIGNAL ;
    SHAPE ABUTMENT ;
    PORT
      LAYER metal3 ;
      RECT 0.000 90.210 0.067 90.277 ;
    END
  END wd_in[81]
  PIN wd_in[82]
    DIRECTION INPUT ;
    USE SIGNAL ;
    SHAPE ABUTMENT ;
    PORT
      LAYER metal3 ;
      RECT 0.000 90.476 0.067 90.543 ;
    END
  END wd_in[82]
  PIN wd_in[83]
    DIRECTION INPUT ;
    USE SIGNAL ;
    SHAPE ABUTMENT ;
    PORT
      LAYER metal3 ;
      RECT 0.000 90.742 0.067 90.809 ;
    END
  END wd_in[83]
  PIN wd_in[84]
    DIRECTION INPUT ;
    USE SIGNAL ;
    SHAPE ABUTMENT ;
    PORT
      LAYER metal3 ;
      RECT 0.000 91.009 0.067 91.075 ;
    END
  END wd_in[84]
  PIN wd_in[85]
    DIRECTION INPUT ;
    USE SIGNAL ;
    SHAPE ABUTMENT ;
    PORT
      LAYER metal3 ;
      RECT 0.000 91.275 0.067 91.341 ;
    END
  END wd_in[85]
  PIN wd_in[86]
    DIRECTION INPUT ;
    USE SIGNAL ;
    SHAPE ABUTMENT ;
    PORT
      LAYER metal3 ;
      RECT 0.000 91.541 0.067 91.607 ;
    END
  END wd_in[86]
  PIN wd_in[87]
    DIRECTION INPUT ;
    USE SIGNAL ;
    SHAPE ABUTMENT ;
    PORT
      LAYER metal3 ;
      RECT 0.000 91.807 0.067 91.873 ;
    END
  END wd_in[87]
  PIN wd_in[88]
    DIRECTION INPUT ;
    USE SIGNAL ;
    SHAPE ABUTMENT ;
    PORT
      LAYER metal3 ;
      RECT 0.000 92.073 0.067 92.140 ;
    END
  END wd_in[88]
  PIN wd_in[89]
    DIRECTION INPUT ;
    USE SIGNAL ;
    SHAPE ABUTMENT ;
    PORT
      LAYER metal3 ;
      RECT 0.000 92.339 0.067 92.406 ;
    END
  END wd_in[89]
  PIN wd_in[90]
    DIRECTION INPUT ;
    USE SIGNAL ;
    SHAPE ABUTMENT ;
    PORT
      LAYER metal3 ;
      RECT 0.000 92.605 0.067 92.672 ;
    END
  END wd_in[90]
  PIN wd_in[91]
    DIRECTION INPUT ;
    USE SIGNAL ;
    SHAPE ABUTMENT ;
    PORT
      LAYER metal3 ;
      RECT 0.000 92.871 0.067 92.938 ;
    END
  END wd_in[91]
  PIN wd_in[92]
    DIRECTION INPUT ;
    USE SIGNAL ;
    SHAPE ABUTMENT ;
    PORT
      LAYER metal3 ;
      RECT 0.000 93.137 0.067 93.204 ;
    END
  END wd_in[92]
  PIN wd_in[93]
    DIRECTION INPUT ;
    USE SIGNAL ;
    SHAPE ABUTMENT ;
    PORT
      LAYER metal3 ;
      RECT 0.000 93.404 0.067 93.470 ;
    END
  END wd_in[93]
  PIN wd_in[94]
    DIRECTION INPUT ;
    USE SIGNAL ;
    SHAPE ABUTMENT ;
    PORT
      LAYER metal3 ;
      RECT 0.000 93.670 0.067 93.736 ;
    END
  END wd_in[94]
  PIN wd_in[95]
    DIRECTION INPUT ;
    USE SIGNAL ;
    SHAPE ABUTMENT ;
    PORT
      LAYER metal3 ;
      RECT 0.000 93.936 0.067 94.002 ;
    END
  END wd_in[95]
  PIN wd_in[96]
    DIRECTION INPUT ;
    USE SIGNAL ;
    SHAPE ABUTMENT ;
    PORT
      LAYER metal3 ;
      RECT 0.000 94.202 0.067 94.268 ;
    END
  END wd_in[96]
  PIN wd_in[97]
    DIRECTION INPUT ;
    USE SIGNAL ;
    SHAPE ABUTMENT ;
    PORT
      LAYER metal3 ;
      RECT 0.000 94.468 0.067 94.534 ;
    END
  END wd_in[97]
  PIN wd_in[98]
    DIRECTION INPUT ;
    USE SIGNAL ;
    SHAPE ABUTMENT ;
    PORT
      LAYER metal3 ;
      RECT 0.000 94.734 0.067 94.801 ;
    END
  END wd_in[98]
  PIN wd_in[99]
    DIRECTION INPUT ;
    USE SIGNAL ;
    SHAPE ABUTMENT ;
    PORT
      LAYER metal3 ;
      RECT 0.000 95.000 0.067 95.067 ;
    END
  END wd_in[99]
  PIN wd_in[100]
    DIRECTION INPUT ;
    USE SIGNAL ;
    SHAPE ABUTMENT ;
    PORT
      LAYER metal3 ;
      RECT 0.000 95.266 0.067 95.333 ;
    END
  END wd_in[100]
  PIN wd_in[101]
    DIRECTION INPUT ;
    USE SIGNAL ;
    SHAPE ABUTMENT ;
    PORT
      LAYER metal3 ;
      RECT 0.000 95.532 0.067 95.599 ;
    END
  END wd_in[101]
  PIN wd_in[102]
    DIRECTION INPUT ;
    USE SIGNAL ;
    SHAPE ABUTMENT ;
    PORT
      LAYER metal3 ;
      RECT 0.000 95.798 0.067 95.865 ;
    END
  END wd_in[102]
  PIN wd_in[103]
    DIRECTION INPUT ;
    USE SIGNAL ;
    SHAPE ABUTMENT ;
    PORT
      LAYER metal3 ;
      RECT 0.000 96.065 0.067 96.131 ;
    END
  END wd_in[103]
  PIN wd_in[104]
    DIRECTION INPUT ;
    USE SIGNAL ;
    SHAPE ABUTMENT ;
    PORT
      LAYER metal3 ;
      RECT 0.000 96.331 0.067 96.397 ;
    END
  END wd_in[104]
  PIN wd_in[105]
    DIRECTION INPUT ;
    USE SIGNAL ;
    SHAPE ABUTMENT ;
    PORT
      LAYER metal3 ;
      RECT 0.000 96.597 0.067 96.663 ;
    END
  END wd_in[105]
  PIN wd_in[106]
    DIRECTION INPUT ;
    USE SIGNAL ;
    SHAPE ABUTMENT ;
    PORT
      LAYER metal3 ;
      RECT 0.000 96.863 0.067 96.929 ;
    END
  END wd_in[106]
  PIN wd_in[107]
    DIRECTION INPUT ;
    USE SIGNAL ;
    SHAPE ABUTMENT ;
    PORT
      LAYER metal3 ;
      RECT 0.000 97.129 0.067 97.196 ;
    END
  END wd_in[107]
  PIN wd_in[108]
    DIRECTION INPUT ;
    USE SIGNAL ;
    SHAPE ABUTMENT ;
    PORT
      LAYER metal3 ;
      RECT 0.000 97.395 0.067 97.462 ;
    END
  END wd_in[108]
  PIN wd_in[109]
    DIRECTION INPUT ;
    USE SIGNAL ;
    SHAPE ABUTMENT ;
    PORT
      LAYER metal3 ;
      RECT 0.000 97.661 0.067 97.728 ;
    END
  END wd_in[109]
  PIN wd_in[110]
    DIRECTION INPUT ;
    USE SIGNAL ;
    SHAPE ABUTMENT ;
    PORT
      LAYER metal3 ;
      RECT 0.000 97.927 0.067 97.994 ;
    END
  END wd_in[110]
  PIN wd_in[111]
    DIRECTION INPUT ;
    USE SIGNAL ;
    SHAPE ABUTMENT ;
    PORT
      LAYER metal3 ;
      RECT 0.000 98.193 0.067 98.260 ;
    END
  END wd_in[111]
  PIN wd_in[112]
    DIRECTION INPUT ;
    USE SIGNAL ;
    SHAPE ABUTMENT ;
    PORT
      LAYER metal3 ;
      RECT 0.000 98.460 0.067 98.526 ;
    END
  END wd_in[112]
  PIN wd_in[113]
    DIRECTION INPUT ;
    USE SIGNAL ;
    SHAPE ABUTMENT ;
    PORT
      LAYER metal3 ;
      RECT 0.000 98.726 0.067 98.792 ;
    END
  END wd_in[113]
  PIN wd_in[114]
    DIRECTION INPUT ;
    USE SIGNAL ;
    SHAPE ABUTMENT ;
    PORT
      LAYER metal3 ;
      RECT 0.000 98.992 0.067 99.058 ;
    END
  END wd_in[114]
  PIN wd_in[115]
    DIRECTION INPUT ;
    USE SIGNAL ;
    SHAPE ABUTMENT ;
    PORT
      LAYER metal3 ;
      RECT 0.000 99.258 0.067 99.324 ;
    END
  END wd_in[115]
  PIN wd_in[116]
    DIRECTION INPUT ;
    USE SIGNAL ;
    SHAPE ABUTMENT ;
    PORT
      LAYER metal3 ;
      RECT 0.000 99.524 0.067 99.591 ;
    END
  END wd_in[116]
  PIN wd_in[117]
    DIRECTION INPUT ;
    USE SIGNAL ;
    SHAPE ABUTMENT ;
    PORT
      LAYER metal3 ;
      RECT 0.000 99.790 0.067 99.857 ;
    END
  END wd_in[117]
  PIN wd_in[118]
    DIRECTION INPUT ;
    USE SIGNAL ;
    SHAPE ABUTMENT ;
    PORT
      LAYER metal3 ;
      RECT 0.000 100.056 0.067 100.123 ;
    END
  END wd_in[118]
  PIN wd_in[119]
    DIRECTION INPUT ;
    USE SIGNAL ;
    SHAPE ABUTMENT ;
    PORT
      LAYER metal3 ;
      RECT 0.000 100.322 0.067 100.389 ;
    END
  END wd_in[119]
  PIN wd_in[120]
    DIRECTION INPUT ;
    USE SIGNAL ;
    SHAPE ABUTMENT ;
    PORT
      LAYER metal3 ;
      RECT 0.000 100.588 0.067 100.655 ;
    END
  END wd_in[120]
  PIN wd_in[121]
    DIRECTION INPUT ;
    USE SIGNAL ;
    SHAPE ABUTMENT ;
    PORT
      LAYER metal3 ;
      RECT 0.000 100.855 0.067 100.921 ;
    END
  END wd_in[121]
  PIN wd_in[122]
    DIRECTION INPUT ;
    USE SIGNAL ;
    SHAPE ABUTMENT ;
    PORT
      LAYER metal3 ;
      RECT 0.000 101.121 0.067 101.187 ;
    END
  END wd_in[122]
  PIN wd_in[123]
    DIRECTION INPUT ;
    USE SIGNAL ;
    SHAPE ABUTMENT ;
    PORT
      LAYER metal3 ;
      RECT 0.000 101.387 0.067 101.453 ;
    END
  END wd_in[123]
  PIN addr_in[0]
    DIRECTION INPUT ;
    USE SIGNAL ;
    SHAPE ABUTMENT ;
    PORT
      LAYER metal3 ;
      RECT 0.000 101.653 0.067 101.719 ;
    END
  END addr_in[0]
  PIN addr_in[1]
    DIRECTION INPUT ;
    USE SIGNAL ;
    SHAPE ABUTMENT ;
    PORT
      LAYER metal3 ;
      RECT 0.000 101.919 0.067 101.985 ;
    END
  END addr_in[1]
  PIN addr_in[2]
    DIRECTION INPUT ;
    USE SIGNAL ;
    SHAPE ABUTMENT ;
    PORT
      LAYER metal3 ;
      RECT 0.000 102.185 0.067 102.252 ;
    END
  END addr_in[2]
  PIN addr_in[3]
    DIRECTION INPUT ;
    USE SIGNAL ;
    SHAPE ABUTMENT ;
    PORT
      LAYER metal3 ;
      RECT 0.000 102.451 0.067 102.518 ;
    END
  END addr_in[3]
  PIN addr_in[4]
    DIRECTION INPUT ;
    USE SIGNAL ;
    SHAPE ABUTMENT ;
    PORT
      LAYER metal3 ;
      RECT 0.000 102.717 0.067 102.784 ;
    END
  END addr_in[4]
  PIN addr_in[5]
    DIRECTION INPUT ;
    USE SIGNAL ;
    SHAPE ABUTMENT ;
    PORT
      LAYER metal3 ;
      RECT 0.000 102.983 0.067 103.050 ;
    END
  END addr_in[5]
  PIN we_in
    DIRECTION INPUT ;
    USE SIGNAL ;
    SHAPE ABUTMENT ;
    PORT
      LAYER metal3 ;
      RECT 0.000 103.249 0.067 103.316 ;
    END
  END we_in
  PIN ce_in
    DIRECTION INPUT ;
    USE SIGNAL ;
    SHAPE ABUTMENT ;
    PORT
      LAYER metal3 ;
      RECT 0.000 103.516 0.067 103.582 ;
    END
  END ce_in
  PIN clk
    DIRECTION INPUT ;
    USE SIGNAL ;
    SHAPE ABUTMENT ;
    PORT
      LAYER metal3 ;
      RECT 0.000 103.782 0.067 103.848 ;
    END
  END clk
  PIN VSS
    DIRECTION INOUT ;
    USE GROUND ;
    PORT
      LAYER metal4 ;
      RECT 2.528 2.661 2.794 104.352 ;
      RECT 6.786 2.661 7.052 104.352 ;
      RECT 11.043 2.661 11.310 104.352 ;
      RECT 15.301 2.661 15.567 104.352 ;
      RECT 19.559 2.661 19.825 104.352 ;
      RECT 23.817 2.661 24.083 104.352 ;
      RECT 28.074 2.661 28.340 104.352 ;
      RECT 32.332 2.661 32.598 104.352 ;
      RECT 36.590 2.661 36.856 104.352 ;
      RECT 40.847 2.661 41.114 104.352 ;
      RECT 45.105 2.661 45.371 104.352 ;
      RECT 49.363 2.661 49.629 104.352 ;
      RECT 53.621 2.661 53.887 104.352 ;
      RECT 57.878 2.661 58.144 104.352 ;
      RECT 62.136 2.661 62.402 104.352 ;
      RECT 66.394 2.661 66.660 104.352 ;
      RECT 70.651 2.661 70.917 104.352 ;
    END
  END VSS
  PIN VDD
    DIRECTION INOUT ;
    USE POWER ;
    PORT
      LAYER metal4 ;
      RECT 4.657 2.661 4.923 104.352 ;
      RECT 8.915 2.661 9.181 104.352 ;
      RECT 13.172 2.661 13.438 104.352 ;
      RECT 17.430 2.661 17.696 104.352 ;
      RECT 21.688 2.661 21.954 104.352 ;
      RECT 25.945 2.661 26.212 104.352 ;
      RECT 30.203 2.661 30.469 104.352 ;
      RECT 34.461 2.661 34.727 104.352 ;
      RECT 38.719 2.661 38.985 104.352 ;
      RECT 42.976 2.661 43.242 104.352 ;
      RECT 47.234 2.661 47.500 104.352 ;
      RECT 51.492 2.661 51.758 104.352 ;
      RECT 55.749 2.661 56.016 104.352 ;
      RECT 60.007 2.661 60.273 104.352 ;
      RECT 64.265 2.661 64.531 104.352 ;
      RECT 68.523 2.661 68.789 104.352 ;
    END
  END VDD
  OBS
    LAYER metal1 ;
    RECT 0.000 0.000 74.215 107.013 ;
    LAYER metal2 ;
    RECT 0.000 0.000 74.215 107.013 ;
    LAYER metal3 ;
    RECT 0.067 0.000 74.215 107.013 ;
    RECT 0.000 0.000 0.067 2.661 ;
    RECT 0.000 2.728 0.067 2.927 ;
    RECT 0.000 2.994 0.067 3.193 ;
    RECT 0.000 3.260 0.067 3.459 ;
    RECT 0.000 3.526 0.067 3.725 ;
    RECT 0.000 3.792 0.067 3.992 ;
    RECT 0.000 4.058 0.067 4.258 ;
    RECT 0.000 4.324 0.067 4.524 ;
    RECT 0.000 4.590 0.067 4.790 ;
    RECT 0.000 4.856 0.067 5.056 ;
    RECT 0.000 5.123 0.067 5.322 ;
    RECT 0.000 5.389 0.067 5.588 ;
    RECT 0.000 5.655 0.067 5.854 ;
    RECT 0.000 5.921 0.067 6.120 ;
    RECT 0.000 6.187 0.067 6.387 ;
    RECT 0.000 6.453 0.067 6.653 ;
    RECT 0.000 6.719 0.067 6.919 ;
    RECT 0.000 6.985 0.067 7.185 ;
    RECT 0.000 7.251 0.067 7.451 ;
    RECT 0.000 7.518 0.067 7.717 ;
    RECT 0.000 7.784 0.067 7.983 ;
    RECT 0.000 8.050 0.067 8.249 ;
    RECT 0.000 8.316 0.067 8.515 ;
    RECT 0.000 8.582 0.067 8.782 ;
    RECT 0.000 8.848 0.067 9.048 ;
    RECT 0.000 9.114 0.067 9.314 ;
    RECT 0.000 9.380 0.067 9.580 ;
    RECT 0.000 9.646 0.067 9.846 ;
    RECT 0.000 9.912 0.067 10.112 ;
    RECT 0.000 10.179 0.067 10.378 ;
    RECT 0.000 10.445 0.067 10.644 ;
    RECT 0.000 10.711 0.067 10.910 ;
    RECT 0.000 10.977 0.067 11.176 ;
    RECT 0.000 11.243 0.067 11.443 ;
    RECT 0.000 11.509 0.067 11.709 ;
    RECT 0.000 11.775 0.067 11.975 ;
    RECT 0.000 12.041 0.067 12.241 ;
    RECT 0.000 12.307 0.067 12.507 ;
    RECT 0.000 12.574 0.067 12.773 ;
    RECT 0.000 12.840 0.067 13.039 ;
    RECT 0.000 13.106 0.067 13.305 ;
    RECT 0.000 13.372 0.067 13.571 ;
    RECT 0.000 13.638 0.067 13.838 ;
    RECT 0.000 13.904 0.067 14.104 ;
    RECT 0.000 14.170 0.067 14.370 ;
    RECT 0.000 14.436 0.067 14.636 ;
    RECT 0.000 14.702 0.067 14.902 ;
    RECT 0.000 14.969 0.067 15.168 ;
    RECT 0.000 15.235 0.067 15.434 ;
    RECT 0.000 15.501 0.067 15.700 ;
    RECT 0.000 15.767 0.067 15.966 ;
    RECT 0.000 16.033 0.067 16.233 ;
    RECT 0.000 16.299 0.067 16.499 ;
    RECT 0.000 16.565 0.067 16.765 ;
    RECT 0.000 16.831 0.067 17.031 ;
    RECT 0.000 17.097 0.067 17.297 ;
    RECT 0.000 17.363 0.067 17.563 ;
    RECT 0.000 17.630 0.067 17.829 ;
    RECT 0.000 17.896 0.067 18.095 ;
    RECT 0.000 18.162 0.067 18.361 ;
    RECT 0.000 18.428 0.067 18.627 ;
    RECT 0.000 18.694 0.067 18.894 ;
    RECT 0.000 18.960 0.067 19.160 ;
    RECT 0.000 19.226 0.067 19.426 ;
    RECT 0.000 19.492 0.067 19.692 ;
    RECT 0.000 19.758 0.067 19.958 ;
    RECT 0.000 20.025 0.067 20.224 ;
    RECT 0.000 20.291 0.067 20.490 ;
    RECT 0.000 20.557 0.067 20.756 ;
    RECT 0.000 20.823 0.067 21.022 ;
    RECT 0.000 21.089 0.067 21.289 ;
    RECT 0.000 21.355 0.067 21.555 ;
    RECT 0.000 21.621 0.067 21.821 ;
    RECT 0.000 21.887 0.067 22.087 ;
    RECT 0.000 22.153 0.067 22.353 ;
    RECT 0.000 22.420 0.067 22.619 ;
    RECT 0.000 22.686 0.067 22.885 ;
    RECT 0.000 22.952 0.067 23.151 ;
    RECT 0.000 23.218 0.067 23.417 ;
    RECT 0.000 23.484 0.067 23.684 ;
    RECT 0.000 23.750 0.067 23.950 ;
    RECT 0.000 24.016 0.067 24.216 ;
    RECT 0.000 24.282 0.067 24.482 ;
    RECT 0.000 24.548 0.067 24.748 ;
    RECT 0.000 24.814 0.067 25.014 ;
    RECT 0.000 25.081 0.067 25.280 ;
    RECT 0.000 25.347 0.067 25.546 ;
    RECT 0.000 25.613 0.067 25.812 ;
    RECT 0.000 25.879 0.067 26.078 ;
    RECT 0.000 26.145 0.067 26.345 ;
    RECT 0.000 26.411 0.067 26.611 ;
    RECT 0.000 26.677 0.067 26.877 ;
    RECT 0.000 26.943 0.067 27.143 ;
    RECT 0.000 27.209 0.067 27.409 ;
    RECT 0.000 27.476 0.067 27.675 ;
    RECT 0.000 27.742 0.067 27.941 ;
    RECT 0.000 28.008 0.067 28.207 ;
    RECT 0.000 28.274 0.067 28.473 ;
    RECT 0.000 28.540 0.067 28.740 ;
    RECT 0.000 28.806 0.067 29.006 ;
    RECT 0.000 29.072 0.067 29.272 ;
    RECT 0.000 29.338 0.067 29.538 ;
    RECT 0.000 29.604 0.067 29.804 ;
    RECT 0.000 29.871 0.067 30.070 ;
    RECT 0.000 30.137 0.067 30.336 ;
    RECT 0.000 30.403 0.067 30.602 ;
    RECT 0.000 30.669 0.067 30.868 ;
    RECT 0.000 30.935 0.067 31.135 ;
    RECT 0.000 31.201 0.067 31.401 ;
    RECT 0.000 31.467 0.067 31.667 ;
    RECT 0.000 31.733 0.067 31.933 ;
    RECT 0.000 31.999 0.067 32.199 ;
    RECT 0.000 32.265 0.067 32.465 ;
    RECT 0.000 32.532 0.067 32.731 ;
    RECT 0.000 32.798 0.067 32.997 ;
    RECT 0.000 33.064 0.067 33.263 ;
    RECT 0.000 33.330 0.067 33.529 ;
    RECT 0.000 33.596 0.067 33.796 ;
    RECT 0.000 33.862 0.067 34.062 ;
    RECT 0.000 34.128 0.067 34.328 ;
    RECT 0.000 34.394 0.067 34.594 ;
    RECT 0.000 34.660 0.067 34.860 ;
    RECT 0.000 34.927 0.067 35.126 ;
    RECT 0.000 35.193 0.067 35.392 ;
    RECT 0.000 35.459 0.067 35.658 ;
    RECT 0.000 35.725 0.067 35.924 ;
    RECT 0.000 35.991 0.067 36.191 ;
    RECT 0.000 36.257 0.067 36.457 ;
    RECT 0.000 36.523 0.067 36.723 ;
    RECT 0.000 36.789 0.067 36.989 ;
    RECT 0.000 37.055 0.067 37.255 ;
    RECT 0.000 37.321 0.067 37.521 ;
    RECT 0.000 37.588 0.067 37.787 ;
    RECT 0.000 37.854 0.067 38.053 ;
    RECT 0.000 38.120 0.067 38.319 ;
    RECT 0.000 38.386 0.067 38.586 ;
    RECT 0.000 38.652 0.067 38.852 ;
    RECT 0.000 38.918 0.067 39.118 ;
    RECT 0.000 39.184 0.067 39.384 ;
    RECT 0.000 39.450 0.067 39.650 ;
    RECT 0.000 39.716 0.067 39.916 ;
    RECT 0.000 39.983 0.067 40.182 ;
    RECT 0.000 40.249 0.067 40.448 ;
    RECT 0.000 40.515 0.067 40.714 ;
    RECT 0.000 40.781 0.067 40.980 ;
    RECT 0.000 41.047 0.067 41.247 ;
    RECT 0.000 41.313 0.067 41.513 ;
    RECT 0.000 41.579 0.067 41.779 ;
    RECT 0.000 41.845 0.067 42.045 ;
    RECT 0.000 42.111 0.067 42.311 ;
    RECT 0.000 42.378 0.067 42.577 ;
    RECT 0.000 42.644 0.067 42.843 ;
    RECT 0.000 42.910 0.067 43.109 ;
    RECT 0.000 43.176 0.067 43.375 ;
    RECT 0.000 43.442 0.067 43.642 ;
    RECT 0.000 43.708 0.067 43.908 ;
    RECT 0.000 43.974 0.067 44.174 ;
    RECT 0.000 44.240 0.067 44.440 ;
    RECT 0.000 44.506 0.067 44.706 ;
    RECT 0.000 44.772 0.067 44.972 ;
    RECT 0.000 45.039 0.067 45.238 ;
    RECT 0.000 45.305 0.067 45.504 ;
    RECT 0.000 45.571 0.067 45.770 ;
    RECT 0.000 45.837 0.067 46.037 ;
    RECT 0.000 46.103 0.067 46.303 ;
    RECT 0.000 46.369 0.067 46.569 ;
    RECT 0.000 46.635 0.067 46.835 ;
    RECT 0.000 46.901 0.067 47.101 ;
    RECT 0.000 47.167 0.067 47.367 ;
    RECT 0.000 47.434 0.067 47.633 ;
    RECT 0.000 47.700 0.067 47.899 ;
    RECT 0.000 47.966 0.067 48.165 ;
    RECT 0.000 48.232 0.067 48.431 ;
    RECT 0.000 48.498 0.067 48.698 ;
    RECT 0.000 48.764 0.067 48.964 ;
    RECT 0.000 49.030 0.067 49.230 ;
    RECT 0.000 49.296 0.067 49.496 ;
    RECT 0.000 49.562 0.067 49.762 ;
    RECT 0.000 49.829 0.067 50.028 ;
    RECT 0.000 50.095 0.067 50.294 ;
    RECT 0.000 50.361 0.067 50.560 ;
    RECT 0.000 50.627 0.067 50.826 ;
    RECT 0.000 50.893 0.067 51.093 ;
    RECT 0.000 51.159 0.067 51.359 ;
    RECT 0.000 51.425 0.067 51.625 ;
    RECT 0.000 51.691 0.067 51.891 ;
    RECT 0.000 51.957 0.067 52.157 ;
    RECT 0.000 52.223 0.067 52.423 ;
    RECT 0.000 52.490 0.067 52.689 ;
    RECT 0.000 52.756 0.067 52.955 ;
    RECT 0.000 53.022 0.067 53.221 ;
    RECT 0.000 53.288 0.067 53.487 ;
    RECT 0.000 53.554 0.067 53.754 ;
    RECT 0.000 53.820 0.067 54.020 ;
    RECT 0.000 54.086 0.067 54.286 ;
    RECT 0.000 54.352 0.067 54.552 ;
    RECT 0.000 54.618 0.067 54.818 ;
    RECT 0.000 54.885 0.067 55.084 ;
    RECT 0.000 55.151 0.067 55.350 ;
    RECT 0.000 55.417 0.067 55.616 ;
    RECT 0.000 55.683 0.067 55.882 ;
    RECT 0.000 55.949 0.067 56.149 ;
    RECT 0.000 56.215 0.067 56.415 ;
    RECT 0.000 56.481 0.067 56.681 ;
    RECT 0.000 56.747 0.067 56.947 ;
    RECT 0.000 57.013 0.067 57.213 ;
    RECT 0.000 57.280 0.067 57.479 ;
    RECT 0.000 57.546 0.067 57.745 ;
    RECT 0.000 57.812 0.067 58.011 ;
    RECT 0.000 58.078 0.067 58.277 ;
    RECT 0.000 58.344 0.067 58.544 ;
    RECT 0.000 58.610 0.067 58.810 ;
    RECT 0.000 58.876 0.067 59.076 ;
    RECT 0.000 59.142 0.067 59.342 ;
    RECT 0.000 59.408 0.067 59.608 ;
    RECT 0.000 59.674 0.067 59.874 ;
    RECT 0.000 59.941 0.067 60.140 ;
    RECT 0.000 60.207 0.067 60.406 ;
    RECT 0.000 60.473 0.067 60.672 ;
    RECT 0.000 60.739 0.067 60.938 ;
    RECT 0.000 61.005 0.067 61.205 ;
    RECT 0.000 61.271 0.067 61.471 ;
    RECT 0.000 61.537 0.067 61.737 ;
    RECT 0.000 61.803 0.067 62.003 ;
    RECT 0.000 62.069 0.067 62.269 ;
    RECT 0.000 62.336 0.067 62.535 ;
    RECT 0.000 62.602 0.067 62.801 ;
    RECT 0.000 62.868 0.067 63.067 ;
    RECT 0.000 63.134 0.067 63.333 ;
    RECT 0.000 63.400 0.067 63.600 ;
    RECT 0.000 63.666 0.067 63.866 ;
    RECT 0.000 63.932 0.067 64.132 ;
    RECT 0.000 64.198 0.067 64.398 ;
    RECT 0.000 64.464 0.067 64.664 ;
    RECT 0.000 64.731 0.067 64.930 ;
    RECT 0.000 64.997 0.067 65.196 ;
    RECT 0.000 65.263 0.067 65.462 ;
    RECT 0.000 65.529 0.067 65.728 ;
    RECT 0.000 65.795 0.067 65.995 ;
    RECT 0.000 66.061 0.067 66.261 ;
    RECT 0.000 66.327 0.067 66.527 ;
    RECT 0.000 66.593 0.067 66.793 ;
    RECT 0.000 66.859 0.067 67.059 ;
    RECT 0.000 67.125 0.067 67.325 ;
    RECT 0.000 67.392 0.067 67.591 ;
    RECT 0.000 67.658 0.067 67.857 ;
    RECT 0.000 67.924 0.067 68.123 ;
    RECT 0.000 68.190 0.067 68.389 ;
    RECT 0.000 68.456 0.067 68.656 ;
    RECT 0.000 68.722 0.067 68.922 ;
    RECT 0.000 68.988 0.067 69.188 ;
    RECT 0.000 69.254 0.067 69.454 ;
    RECT 0.000 69.520 0.067 69.720 ;
    RECT 0.000 69.787 0.067 69.986 ;
    RECT 0.000 70.053 0.067 70.252 ;
    RECT 0.000 70.319 0.067 70.518 ;
    RECT 0.000 70.585 0.067 70.784 ;
    RECT 0.000 70.851 0.067 71.051 ;
    RECT 0.000 71.117 0.067 71.317 ;
    RECT 0.000 71.383 0.067 71.583 ;
    RECT 0.000 71.649 0.067 71.849 ;
    RECT 0.000 71.915 0.067 72.115 ;
    RECT 0.000 72.182 0.067 72.381 ;
    RECT 0.000 72.448 0.067 72.647 ;
    RECT 0.000 72.714 0.067 72.913 ;
    RECT 0.000 72.980 0.067 73.179 ;
    RECT 0.000 73.246 0.067 73.446 ;
    RECT 0.000 73.512 0.067 73.712 ;
    RECT 0.000 73.778 0.067 73.978 ;
    RECT 0.000 74.044 0.067 74.244 ;
    RECT 0.000 74.310 0.067 74.510 ;
    RECT 0.000 74.576 0.067 74.776 ;
    RECT 0.000 74.843 0.067 75.042 ;
    RECT 0.000 75.109 0.067 75.308 ;
    RECT 0.000 75.375 0.067 75.574 ;
    RECT 0.000 75.641 0.067 75.840 ;
    RECT 0.000 75.907 0.067 76.107 ;
    RECT 0.000 76.173 0.067 76.373 ;
    RECT 0.000 76.439 0.067 76.639 ;
    RECT 0.000 76.705 0.067 76.905 ;
    RECT 0.000 76.971 0.067 77.171 ;
    RECT 0.000 77.238 0.067 77.437 ;
    RECT 0.000 77.504 0.067 77.703 ;
    RECT 0.000 77.770 0.067 77.969 ;
    RECT 0.000 78.036 0.067 78.235 ;
    RECT 0.000 78.302 0.067 78.502 ;
    RECT 0.000 78.568 0.067 78.768 ;
    RECT 0.000 78.834 0.067 79.034 ;
    RECT 0.000 79.100 0.067 79.300 ;
    RECT 0.000 79.366 0.067 79.566 ;
    RECT 0.000 79.633 0.067 79.832 ;
    RECT 0.000 79.899 0.067 80.098 ;
    RECT 0.000 80.165 0.067 80.364 ;
    RECT 0.000 80.431 0.067 80.630 ;
    RECT 0.000 80.697 0.067 80.897 ;
    RECT 0.000 80.963 0.067 81.163 ;
    RECT 0.000 81.229 0.067 81.429 ;
    RECT 0.000 81.495 0.067 81.695 ;
    RECT 0.000 81.761 0.067 81.961 ;
    RECT 0.000 82.027 0.067 82.227 ;
    RECT 0.000 82.294 0.067 82.493 ;
    RECT 0.000 82.560 0.067 82.759 ;
    RECT 0.000 82.826 0.067 83.025 ;
    RECT 0.000 83.092 0.067 83.291 ;
    RECT 0.000 83.358 0.067 83.558 ;
    RECT 0.000 83.624 0.067 83.824 ;
    RECT 0.000 83.890 0.067 84.090 ;
    RECT 0.000 84.156 0.067 84.356 ;
    RECT 0.000 84.422 0.067 84.622 ;
    RECT 0.000 84.689 0.067 84.888 ;
    RECT 0.000 84.955 0.067 85.154 ;
    RECT 0.000 85.221 0.067 85.420 ;
    RECT 0.000 85.487 0.067 85.686 ;
    RECT 0.000 85.753 0.067 85.953 ;
    RECT 0.000 86.019 0.067 86.219 ;
    RECT 0.000 86.285 0.067 86.485 ;
    RECT 0.000 86.551 0.067 86.751 ;
    RECT 0.000 86.817 0.067 87.017 ;
    RECT 0.000 87.083 0.067 87.283 ;
    RECT 0.000 87.350 0.067 87.549 ;
    RECT 0.000 87.616 0.067 87.815 ;
    RECT 0.000 87.882 0.067 88.081 ;
    RECT 0.000 88.148 0.067 88.348 ;
    RECT 0.000 88.414 0.067 88.614 ;
    RECT 0.000 88.680 0.067 88.880 ;
    RECT 0.000 88.946 0.067 89.146 ;
    RECT 0.000 89.212 0.067 89.412 ;
    RECT 0.000 89.478 0.067 89.678 ;
    RECT 0.000 89.745 0.067 89.944 ;
    RECT 0.000 90.011 0.067 90.210 ;
    RECT 0.000 90.277 0.067 90.476 ;
    RECT 0.000 90.543 0.067 90.742 ;
    RECT 0.000 90.809 0.067 91.009 ;
    RECT 0.000 91.075 0.067 91.275 ;
    RECT 0.000 91.341 0.067 91.541 ;
    RECT 0.000 91.607 0.067 91.807 ;
    RECT 0.000 91.873 0.067 92.073 ;
    RECT 0.000 92.140 0.067 92.339 ;
    RECT 0.000 92.406 0.067 92.605 ;
    RECT 0.000 92.672 0.067 92.871 ;
    RECT 0.000 92.938 0.067 93.137 ;
    RECT 0.000 93.204 0.067 93.404 ;
    RECT 0.000 93.470 0.067 93.670 ;
    RECT 0.000 93.736 0.067 93.936 ;
    RECT 0.000 94.002 0.067 94.202 ;
    RECT 0.000 94.268 0.067 94.468 ;
    RECT 0.000 94.534 0.067 94.734 ;
    RECT 0.000 94.801 0.067 95.000 ;
    RECT 0.000 95.067 0.067 95.266 ;
    RECT 0.000 95.333 0.067 95.532 ;
    RECT 0.000 95.599 0.067 95.798 ;
    RECT 0.000 95.865 0.067 96.065 ;
    RECT 0.000 96.131 0.067 96.331 ;
    RECT 0.000 96.397 0.067 96.597 ;
    RECT 0.000 96.663 0.067 96.863 ;
    RECT 0.000 96.929 0.067 97.129 ;
    RECT 0.000 97.196 0.067 97.395 ;
    RECT 0.000 97.462 0.067 97.661 ;
    RECT 0.000 97.728 0.067 97.927 ;
    RECT 0.000 97.994 0.067 98.193 ;
    RECT 0.000 98.260 0.067 98.460 ;
    RECT 0.000 98.526 0.067 98.726 ;
    RECT 0.000 98.792 0.067 98.992 ;
    RECT 0.000 99.058 0.067 99.258 ;
    RECT 0.000 99.324 0.067 99.524 ;
    RECT 0.000 99.591 0.067 99.790 ;
    RECT 0.000 99.857 0.067 100.056 ;
    RECT 0.000 100.123 0.067 100.322 ;
    RECT 0.000 100.389 0.067 100.588 ;
    RECT 0.000 100.655 0.067 100.855 ;
    RECT 0.000 100.921 0.067 101.121 ;
    RECT 0.000 101.187 0.067 101.387 ;
    RECT 0.000 101.453 0.067 101.653 ;
    RECT 0.000 101.719 0.067 101.919 ;
    RECT 0.000 101.985 0.067 102.185 ;
    RECT 0.000 102.252 0.067 102.451 ;
    RECT 0.000 102.518 0.067 102.717 ;
    RECT 0.000 102.784 0.067 102.983 ;
    RECT 0.000 103.050 0.067 103.249 ;
    RECT 0.000 103.316 0.067 103.516 ;
    RECT 0.000 103.582 0.067 103.782 ;
    RECT 0.000 103.848 0.067 107.013 ;
    LAYER metal4 ;
    RECT 0.000 0.000 74.215 2.661 ;
    RECT 0.000 104.352 74.215 107.013 ;
    RECT 0.000 2.661 2.528 104.352 ;
    RECT 2.794 2.661 4.657 104.352 ;
    RECT 4.923 2.661 6.786 104.352 ;
    RECT 7.052 2.661 8.915 104.352 ;
    RECT 9.181 2.661 11.043 104.352 ;
    RECT 11.310 2.661 13.172 104.352 ;
    RECT 13.438 2.661 15.301 104.352 ;
    RECT 15.567 2.661 17.430 104.352 ;
    RECT 17.696 2.661 19.559 104.352 ;
    RECT 19.825 2.661 21.688 104.352 ;
    RECT 21.954 2.661 23.817 104.352 ;
    RECT 24.083 2.661 25.945 104.352 ;
    RECT 26.212 2.661 28.074 104.352 ;
    RECT 28.340 2.661 30.203 104.352 ;
    RECT 30.469 2.661 32.332 104.352 ;
    RECT 32.598 2.661 34.461 104.352 ;
    RECT 34.727 2.661 36.590 104.352 ;
    RECT 36.856 2.661 38.719 104.352 ;
    RECT 38.985 2.661 40.847 104.352 ;
    RECT 41.114 2.661 42.976 104.352 ;
    RECT 43.242 2.661 45.105 104.352 ;
    RECT 45.371 2.661 47.234 104.352 ;
    RECT 47.500 2.661 49.363 104.352 ;
    RECT 49.629 2.661 51.492 104.352 ;
    RECT 51.758 2.661 53.621 104.352 ;
    RECT 53.887 2.661 55.749 104.352 ;
    RECT 56.016 2.661 57.878 104.352 ;
    RECT 58.144 2.661 60.007 104.352 ;
    RECT 60.273 2.661 62.136 104.352 ;
    RECT 62.402 2.661 64.265 104.352 ;
    RECT 64.531 2.661 66.394 104.352 ;
    RECT 66.660 2.661 68.523 104.352 ;
    RECT 68.789 2.661 70.651 104.352 ;
    RECT 70.917 2.661 74.215 104.352 ;
  END
END fakeram45_64x112

END LIBRARY
